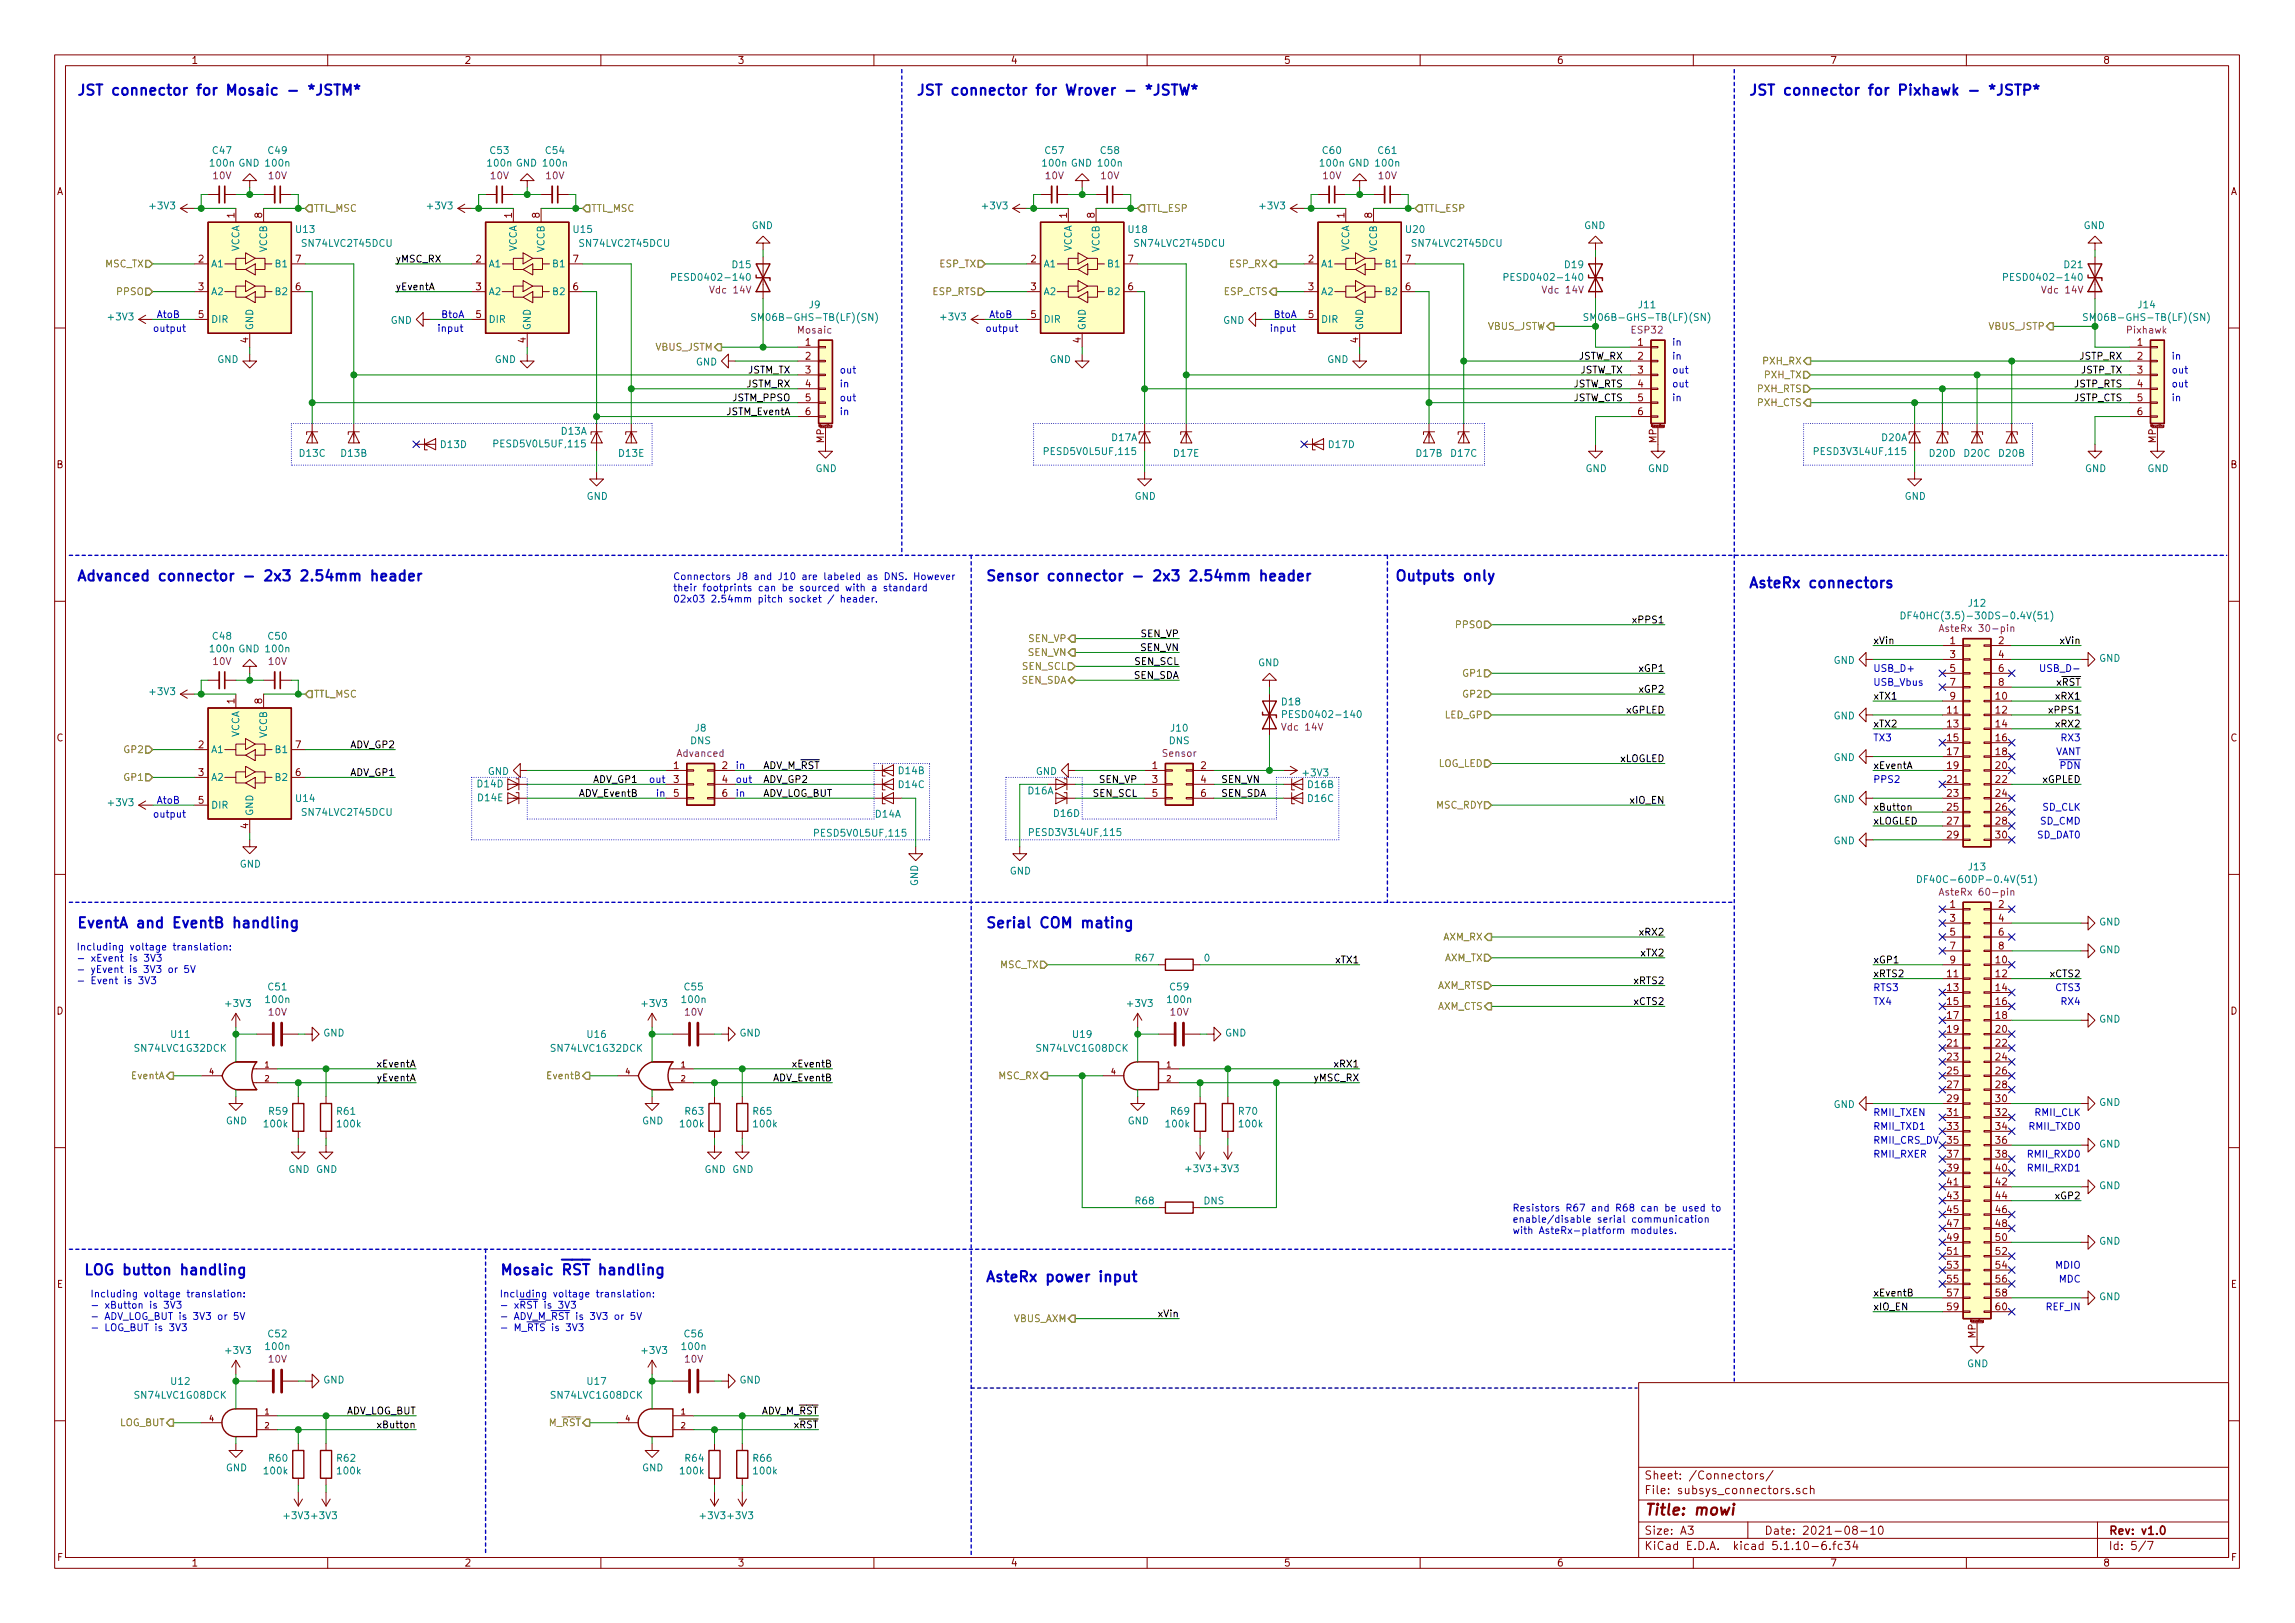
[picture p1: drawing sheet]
<svg xmlns="http://www.w3.org/2000/svg" width="420mm" height="297mm" viewBox="0 0 420 297" stroke-linecap="round" stroke-linejoin="round" font-family="sans-serif">
<defs><g id="words">
<text font-size="2.8" fill="#840000" x="301" y="277.3">Title: mowi</text>
<g font-size="2.7" fill="#0000c2">
<text x="14" y="17.5">JST connector for Mosaic - *JSTM*</text>
<text x="167.6" y="17.5">JST connector for Wrover - *JSTW*</text>
<text x="320" y="17.5">JST connector for Pixhawk - *JSTP*</text>
<text x="14" y="106.4">Advanced connector - 2x3 2.54mm header</text>
<text x="180.3" y="106.4">Sensor connector - 2x3 2.54mm header</text>
<text x="255.3" y="106.4">Outputs only</text>
<text x="320" y="107.6">AsteRx connectors</text>
<text x="14" y="169.9">EventA and EventB handling</text>
<text x="180.3" y="169.9">Serial COM mating</text>
<text x="15.2" y="233.4">LOG button handling</text>
<text x="91.4" y="233.4">Mosaic RST handling</text>
<text x="180.3" y="234.6">AsteRx power input</text>
</g>
<g font-size="2.1" fill="#840000">
<text x="301" y="273.5">File: subsys_connectors.sch</text>
<text x="301" y="270.8">Sheet: /Connectors/</text>
<text x="301" y="280.9">Size: A3</text>
<text x="323" y="280.9">Date: 2021-08-10</text>
<text x="386" y="280.9">Rev: v1.0</text>
<text x="301" y="283.7">KiCad E.D.A. kicad 5.1.10-6.fc34</text>
<text x="386" y="283.7">Id: 5/7</text>
</g>
<g font-size="1.8" fill="#840000">
<text x="35" y="11.7">1</text>
<text x="85" y="11.7">2</text>
<text x="135" y="11.7">3</text>
<text x="185" y="11.7">4</text>
<text x="235" y="11.7">5</text>
<text x="285" y="11.7">6</text>
<text x="335" y="11.7">7</text>
<text x="385" y="11.7">8</text>
<text x="10.4" y="35.7">A</text>
<text x="408.4" y="35.7">A</text>
<text x="42.9" y="39.9" transform="rotate(-90 42.9 39.9)">1</text>
<text x="48" y="39.9" transform="rotate(-90 48 39.9)">8</text>
<text x="93.7" y="39.9" transform="rotate(-90 93.7 39.9)">1</text>
<text x="98.8" y="39.9" transform="rotate(-90 98.8 39.9)">8</text>
<text x="195.3" y="39.9" transform="rotate(-90 195.3 39.9)">1</text>
<text x="200.4" y="39.9" transform="rotate(-90 200.4 39.9)">8</text>
<text x="246.1" y="39.9" transform="rotate(-90 246.1 39.9)">1</text>
<text x="251.2" y="39.9" transform="rotate(-90 251.2 39.9)">8</text>
<text x="36.3" y="48">2</text>
<text x="36.3" y="53.1">3</text>
<text x="54.1" y="53.1">6</text>
<text x="54.1" y="48">7</text>
<text x="87.1" y="48">2</text>
<text x="87.1" y="53.1">3</text>
<text x="104.9" y="53.1">6</text>
<text x="104.9" y="48">7</text>
<text x="188.7" y="48">2</text>
<text x="188.7" y="53.1">3</text>
<text x="206.5" y="53.1">6</text>
<text x="206.5" y="48">7</text>
<text x="239.5" y="48">2</text>
<text x="239.5" y="53.1">3</text>
<text x="257.3" y="53.1">6</text>
<text x="257.3" y="48">7</text>
<text x="36.3" y="58.2">5</text>
<text x="87.1" y="58.2">5</text>
<text x="188.7" y="58.2">5</text>
<text x="239.5" y="58.2">5</text>
<text x="45.5" y="62.7" transform="rotate(-90 45.5 62.7)">4</text>
<text x="96.3" y="62.7" transform="rotate(-90 96.3 62.7)">4</text>
<text x="147.5" y="63.3">1</text>
<text x="147.5" y="65.8">2</text>
<text x="197.9" y="62.7" transform="rotate(-90 197.9 62.7)">4</text>
<text x="248.7" y="62.7" transform="rotate(-90 248.7 62.7)">4</text>
<text x="299.9" y="63.3">1</text>
<text x="299.9" y="65.8">2</text>
<text x="391.3" y="63.3">1</text>
<text x="391.3" y="65.8">2</text>
<text x="147.5" y="68.4">3</text>
<text x="147.5" y="70.9">4</text>
<text x="299.9" y="68.4">3</text>
<text x="299.9" y="70.9">4</text>
<text x="391.3" y="68.4">3</text>
<text x="391.3" y="70.9">4</text>
<text x="147.5" y="73.4">5</text>
<text x="147.5" y="76">6</text>
<text x="299.9" y="73.4">5</text>
<text x="299.9" y="76">6</text>
<text x="391.3" y="73.4">5</text>
<text x="391.3" y="76">6</text>
<text x="150.9" y="81.1" transform="rotate(-90 150.9 81.1)">MP</text>
<text x="303.3" y="81.1" transform="rotate(-90 303.3 81.1)">MP</text>
<text x="394.7" y="81.1" transform="rotate(-90 394.7 81.1)">MP</text>
<text x="10.4" y="85.7">B</text>
<text x="408.4" y="85.7">B</text>
<text x="357" y="117.9">1</text>
<text x="365.9" y="117.9">2</text>
<text x="357" y="120.4">3</text>
<text x="357" y="123">5</text>
<text x="357" y="125.5">7</text>
<text x="365.9" y="120.4">4</text>
<text x="365.9" y="123">6</text>
<text x="365.9" y="125.5">8</text>
<text x="42.9" y="128.8" transform="rotate(-90 42.9 128.8)">1</text>
<text x="48" y="128.8" transform="rotate(-90 48 128.8)">8</text>
<text x="356.5" y="130.6">11</text>
<text x="357" y="128.1">9</text>
<text x="365.4" y="128.1">10</text>
<text x="365.4" y="130.6">12</text>
<text x="10.4" y="135.7">C</text>
<text x="36.3" y="136.9">2</text>
<text x="54.1" y="136.9">7</text>
<text x="356.5" y="133.1">13</text>
<text x="356.5" y="135.7">15</text>
<text x="365.4" y="133.1">14</text>
<text x="365.4" y="135.7">16</text>
<text x="408.4" y="135.7">C</text>
<text x="36.3" y="142">3</text>
<text x="54.1" y="142">6</text>
<text x="123.3" y="140.8">1</text>
<text x="123.3" y="143.3">3</text>
<text x="132.2" y="140.8">2</text>
<text x="132.2" y="143.3">4</text>
<text x="211" y="140.8">1</text>
<text x="211" y="143.3">3</text>
<text x="219.9" y="140.8">2</text>
<text x="219.9" y="143.3">4</text>
<text x="356.5" y="138.2">17</text>
<text x="356.5" y="140.8">19</text>
<text x="356.5" y="143.3">21</text>
<text x="365.4" y="138.2">18</text>
<text x="365.4" y="140.8">20</text>
<text x="365.4" y="143.3">22</text>
<text x="36.3" y="147.1">5</text>
<text x="123.3" y="145.8">5</text>
<text x="132.2" y="145.8">6</text>
<text x="211" y="145.8">5</text>
<text x="219.9" y="145.8">6</text>
<text x="356.5" y="145.8">23</text>
<text x="356.5" y="148.4">25</text>
<text x="365.4" y="145.8">24</text>
<text x="365.4" y="148.4">26</text>
<text x="45.5" y="151.6" transform="rotate(-90 45.5 151.6)">4</text>
<text x="356.5" y="150.9">27</text>
<text x="356.5" y="153.5">29</text>
<text x="365.4" y="150.9">28</text>
<text x="365.4" y="153.5">30</text>
<text x="357" y="166.2">1</text>
<text x="365.9" y="166.2">2</text>
<text x="357" y="168.7">3</text>
<text x="357" y="171.2">5</text>
<text x="357" y="173.8">7</text>
<text x="365.9" y="168.7">4</text>
<text x="365.9" y="171.2">6</text>
<text x="365.9" y="173.8">8</text>
<text x="356.5" y="178.9">11</text>
<text x="357" y="176.3">9</text>
<text x="365.4" y="176.3">10</text>
<text x="365.4" y="178.9">12</text>
<text x="10.4" y="185.7">D</text>
<text x="356.5" y="181.4">13</text>
<text x="356.5" y="183.9">15</text>
<text x="365.4" y="181.4">14</text>
<text x="365.4" y="183.9">16</text>
<text x="408.4" y="185.7">D</text>
<text x="356.5" y="186.5">17</text>
<text x="356.5" y="189">19</text>
<text x="356.5" y="191.6">21</text>
<text x="365.4" y="186.5">18</text>
<text x="365.4" y="189">20</text>
<text x="365.4" y="191.6">22</text>
<text x="356.5" y="194.1">23</text>
<text x="356.5" y="196.6">25</text>
<text x="365.4" y="194.1">24</text>
<text x="365.4" y="196.6">26</text>
<text x="356.5" y="199.2">27</text>
<text x="356.5" y="201.7">29</text>
<text x="365.4" y="199.2">28</text>
<text x="365.4" y="201.7">30</text>
<text x="356.5" y="204.3">31</text>
<text x="356.5" y="206.8">33</text>
<text x="356.5" y="209.3">35</text>
<text x="365.4" y="204.3">32</text>
<text x="365.4" y="206.8">34</text>
<text x="365.4" y="209.3">36</text>
<text x="356.5" y="211.9">37</text>
<text x="356.5" y="214.4">39</text>
<text x="365.4" y="211.9">38</text>
<text x="365.4" y="214.4">40</text>
<text x="356.5" y="217">41</text>
<text x="356.5" y="219.5">43</text>
<text x="365.4" y="217">42</text>
<text x="365.4" y="219.5">44</text>
<text x="356.5" y="222">45</text>
<text x="356.5" y="224.6">47</text>
<text x="356.5" y="227.1">49</text>
<text x="365.4" y="222">46</text>
<text x="365.4" y="224.6">48</text>
<text x="365.4" y="227.1">50</text>
<text x="356.5" y="229.7">51</text>
<text x="356.5" y="232.2">53</text>
<text x="365.4" y="229.7">52</text>
<text x="365.4" y="232.2">54</text>
<text x="10.4" y="235.7">E</text>
<text x="356.5" y="234.7">55</text>
<text x="356.5" y="237.3">57</text>
<text x="356.5" y="239.8">59</text>
<text x="365.4" y="234.7">56</text>
<text x="365.4" y="237.3">58</text>
<text x="365.4" y="239.8">60</text>
<text x="408.4" y="235.7">E</text>
<text x="361.7" y="244.9" transform="rotate(-90 361.7 244.9)">MP</text>
<text x="10.5" y="285.7">F</text>
<text x="35" y="286.7">1</text>
<text x="85" y="286.7">2</text>
<text x="135" y="286.7">3</text>
<text x="185" y="286.7">4</text>
<text x="235" y="286.7">5</text>
<text x="285" y="286.7">6</text>
<text x="335" y="286.7">7</text>
<text x="385" y="286.7">8</text>
<text x="408.5" y="285.7">F</text>
</g>
<g font-size="1.8" fill="#008484">
<text x="39" y="28.2">C47</text>
<text x="49.2" y="28.2">C49</text>
<text x="89.8" y="28.2">C53</text>
<text x="100" y="28.2">C54</text>
<text x="191.4" y="28.2">C57</text>
<text x="201.6" y="28.2">C58</text>
<text x="242.2" y="28.2">C60</text>
<text x="252.4" y="28.2">C61</text>
<text x="38.6" y="30.5">100n GND 100n</text>
<text x="89.4" y="30.5">100n GND 100n</text>
<text x="191" y="30.5">100n GND 100n</text>
<text x="241.8" y="30.5">100n GND 100n</text>
<text x="27.6" y="38.3">+3V3</text>
<text x="78.4" y="38.3">+3V3</text>
<text x="137.6" y="41.9">GND</text>
<text x="180" y="38.3">+3V3</text>
<text x="230.8" y="38.3">+3V3</text>
<text x="290" y="41.9">GND</text>
<text x="381.5" y="41.9">GND</text>
<text x="43.8" y="46.2" transform="rotate(-90 43.8 46.2)">VCCA</text>
<text x="48.9" y="46.2" transform="rotate(-90 48.9 46.2)">VCCB</text>
<text x="54.3" y="42.6">U13</text>
<text x="55.6" y="45.2">SN74LVC2T45DCU</text>
<text x="94.6" y="46.2" transform="rotate(-90 94.6 46.2)">VCCA</text>
<text x="99.7" y="46.2" transform="rotate(-90 99.7 46.2)">VCCB</text>
<text x="105.1" y="42.6">U15</text>
<text x="106.4" y="45.2">SN74LVC2T45DCU</text>
<text x="196.2" y="46.2" transform="rotate(-90 196.2 46.2)">VCCA</text>
<text x="201.3" y="46.2" transform="rotate(-90 201.3 46.2)">VCCB</text>
<text x="206.7" y="42.6">U18</text>
<text x="208" y="45.2">SN74LVC2T45DCU</text>
<text x="247" y="46.2" transform="rotate(-90 247 46.2)">VCCA</text>
<text x="252.1" y="46.2" transform="rotate(-90 252.1 46.2)">VCCB</text>
<text x="257.5" y="42.6">U20</text>
<text x="258.8" y="45.2">SN74LVC2T45DCU</text>
<text x="38.6" y="48.9">A1</text>
<text x="50.6" y="48.9">B1</text>
<text x="89.4" y="48.9">A1</text>
<text x="101.4" y="48.9">B1</text>
<text x="124" y="51.4">PESD0402-140</text>
<text x="134.1" y="49.1">D15</text>
<text x="191" y="48.9">A1</text>
<text x="203" y="48.9">B1</text>
<text x="241.8" y="48.9">A1</text>
<text x="253.8" y="48.9">B1</text>
<text x="276.4" y="51.4">PESD0402-140</text>
<text x="286.5" y="49.1">D19</text>
<text x="367.8" y="51.4">PESD0402-140</text>
<text x="378" y="49.1">D21</text>
<text x="20" y="58.6">+3V3</text>
<text x="38.6" y="54">A2</text>
<text x="38.6" y="59.1">DIR</text>
<text x="50.6" y="54">B2</text>
<text x="71.5" y="59.3">GND</text>
<text x="89.4" y="54">A2</text>
<text x="89.4" y="59.1">DIR</text>
<text x="101.4" y="54">B2</text>
<text x="139" y="58.7">SM06B-GHS-TB(LF)(SN)</text>
<text x="148.2" y="56.4">J9</text>
<text x="172.4" y="58.6">+3V3</text>
<text x="191" y="54">A2</text>
<text x="191" y="59.1">DIR</text>
<text x="203" y="54">B2</text>
<text x="223.9" y="59.3">GND</text>
<text x="241.8" y="54">A2</text>
<text x="241.8" y="59.1">DIR</text>
<text x="253.8" y="54">B2</text>
<text x="291.4" y="58.7">SM06B-GHS-TB(LF)(SN)</text>
<text x="300.1" y="56.4">J11</text>
<text x="382.9" y="58.7">SM06B-GHS-TB(LF)(SN)</text>
<text x="391.5" y="56.4">J14</text>
<text x="46.4" y="60.5" transform="rotate(-90 46.4 60.5)">GND</text>
<text x="97.2" y="60.5" transform="rotate(-90 97.2 60.5)">GND</text>
<text x="198.8" y="60.5" transform="rotate(-90 198.8 60.5)">GND</text>
<text x="249.6" y="60.5" transform="rotate(-90 249.6 60.5)">GND</text>
<text x="39.8" y="66.4">GND</text>
<text x="90.6" y="66.4">GND</text>
<text x="127.4" y="66.9">GND</text>
<text x="192.2" y="66.4">GND</text>
<text x="243" y="66.4">GND</text>
<text x="54.9" y="83.6">D13C</text>
<text x="62.5" y="83.6">D13B</text>
<text x="80.7" y="82">D13D</text>
<text x="90.9" y="81.9">PESD5V0L5UF,115</text>
<text x="102.8" y="79.6">D13A</text>
<text x="113.4" y="83.6">D13E</text>
<text x="191.6" y="83.3">PESD5V0L5UF,115</text>
<text x="203.6" y="80.7">D17A</text>
<text x="215" y="83.6">D17E</text>
<text x="243.3" y="82">D17D</text>
<text x="259.4" y="83.6">D17B</text>
<text x="265.7" y="83.6">D17C</text>
<text x="332.6" y="83.3">PESD3V3L4UF,115</text>
<text x="344.5" y="80.7">D20A</text>
<text x="353.3" y="83.6">D20D</text>
<text x="359.7" y="83.6">D20C</text>
<text x="366" y="83.6">D20B</text>
<text x="149.3" y="86.4">GND</text>
<text x="290.3" y="86.4">GND</text>
<text x="301.7" y="86.4">GND</text>
<text x="381.7" y="86.4">GND</text>
<text x="393.1" y="86.4">GND</text>
<text x="107.4" y="91.5">GND</text>
<text x="207.7" y="91.5">GND</text>
<text x="348.7" y="91.5">GND</text>
<text x="350.5" y="113.3">DF40HC(3.5)-30DS-0.4V(51)</text>
<text x="360.5" y="111">J12</text>
<text x="38.6" y="119.4">100n GND 100n</text>
<text x="39" y="117.1">C48</text>
<text x="49.2" y="117.1">C50</text>
<text x="230.3" y="121.9">GND</text>
<text x="335.7" y="121.5">GND</text>
<text x="384.3" y="121.1">GND</text>
<text x="27.6" y="127.2">+3V3</text>
<text x="234.7" y="129.1">D18</text>
<text x="235.8" y="131.4">PESD0402-140</text>
<text x="335.7" y="131.7">GND</text>
<text x="38.6" y="137.8">A1</text>
<text x="43.8" y="135.1" transform="rotate(-90 43.8 135.1)">VCCA</text>
<text x="48.9" y="135.1" transform="rotate(-90 48.9 135.1)">VCCB</text>
<text x="50.6" y="137.8">B1</text>
<text x="126.4" y="136.2">DNS</text>
<text x="127.3" y="133.9">J8</text>
<text x="214" y="136.2">DNS</text>
<text x="214.4" y="133.9">J10</text>
<text x="38.6" y="142.9">A2</text>
<text x="50.6" y="142.9">B2</text>
<text x="89.3" y="141.8">GND</text>
<text x="164.6" y="141.7">D14B</text>
<text x="189.6" y="141.8">GND</text>
<text x="238.7" y="142.1">+3V3</text>
<text x="335.7" y="139.3">GND</text>
<text x="20" y="147.5">+3V3</text>
<text x="38.6" y="148">DIR</text>
<text x="46.4" y="149.4" transform="rotate(-90 46.4 149.4)">GND</text>
<text x="54.3" y="146.8">U14</text>
<text x="55.6" y="149.3">SN74LVC2T45DCU</text>
<text x="87.5" y="144.1">D14D</text>
<text x="87.6" y="146.6">D14E</text>
<text x="160.3" y="149.6">D14A</text>
<text x="164.6" y="144.2">D14C</text>
<text x="188.2" y="145.4">D16A</text>
<text x="193" y="149.5">D16D</text>
<text x="239.5" y="146.8">D16C</text>
<text x="239.5" y="144.2">D16B</text>
<text x="335.7" y="146.9">GND</text>
<text x="149.6" y="153.1">PESD5V0L5UF,115</text>
<text x="188.9" y="153">PESD3V3L4UF,115</text>
<text x="335.7" y="154.5">GND</text>
<text x="43.9" y="158.8">GND</text>
<text x="184.9" y="160.1">GND</text>
<text x="353" y="161.6">DF40C-60DP-0.4V(51)</text>
<text x="360.5" y="159.3">J13</text>
<text x="168.1" y="162.2" transform="rotate(-90 168.1 162.2)">GND</text>
<text x="384.3" y="169.4">GND</text>
<text x="207.9" y="176">R67</text>
<text x="220.5" y="176">0</text>
<text x="384.3" y="174.5">GND</text>
<text x="41.5" y="184.3">+3V3</text>
<text x="48.8" y="183.6">100n</text>
<text x="49.2" y="181.3">C51</text>
<text x="117.7" y="184.3">+3V3</text>
<text x="125" y="183.6">100n</text>
<text x="125.4" y="181.3">C55</text>
<text x="206.6" y="184.3">+3V3</text>
<text x="213.9" y="183.6">100n</text>
<text x="214.3" y="181.3">C59</text>
<text x="31.4" y="190">U11</text>
<text x="59.2" y="189.7">GND</text>
<text x="107.6" y="190">U16</text>
<text x="135.4" y="189.7">GND</text>
<text x="196.5" y="190">U19</text>
<text x="224.3" y="189.7">GND</text>
<text x="384.3" y="187.2">GND</text>
<text x="24.9" y="192.5">SN74LVC1G32DCK</text>
<text x="101.1" y="192.5">SN74LVC1G32DCK</text>
<text x="190" y="192.5">SN74LVC1G08DCK</text>
<text x="335.7" y="202.8">GND</text>
<text x="384.3" y="202.4">GND</text>
<text x="41.4" y="205.8">GND</text>
<text x="48.5" y="206.3">100k</text>
<text x="49.3" y="204">R59</text>
<text x="61.7" y="204">R61</text>
<text x="61.9" y="206.3">100k</text>
<text x="117.6" y="205.8">GND</text>
<text x="124.7" y="206.3">100k</text>
<text x="125.5" y="204">R63</text>
<text x="137.9" y="204">R65</text>
<text x="138.1" y="206.3">100k</text>
<text x="206.5" y="205.8">GND</text>
<text x="213.6" y="206.3">100k</text>
<text x="214.4" y="204">R69</text>
<text x="226.8" y="204">R70</text>
<text x="227" y="206.3">100k</text>
<text x="52.8" y="214.7">GND GND</text>
<text x="129" y="214.7">GND GND</text>
<text x="217.2" y="214.5">+3V3 +3V3</text>
<text x="384.3" y="210">GND</text>
<text x="207.9" y="220.4">R68</text>
<text x="220.4" y="220.4">DNS</text>
<text x="384.3" y="217.6">GND</text>
<text x="384.3" y="227.8">GND</text>
<text x="384.3" y="238">GND</text>
<text x="49.2" y="244.8">C52</text>
<text x="125.4" y="244.8">C56</text>
<text x="41.5" y="247.8">+3V3</text>
<text x="48.8" y="247.1">100n</text>
<text x="117.7" y="247.8">+3V3</text>
<text x="125" y="247.1">100n</text>
<text x="360.1" y="250.2">GND</text>
<text x="24.9" y="256">SN74LVC1G08DCK</text>
<text x="31.4" y="253.5">U12</text>
<text x="59.2" y="253.2">GND</text>
<text x="101.1" y="256">SN74LVC1G08DCK</text>
<text x="107.6" y="253.5">U17</text>
<text x="135.4" y="253.2">GND</text>
<text x="41.4" y="269.3">GND</text>
<text x="48.5" y="269.8">100k</text>
<text x="49.3" y="267.5">R60</text>
<text x="61.7" y="267.5">R62</text>
<text x="61.9" y="269.8">100k</text>
<text x="117.6" y="269.3">GND</text>
<text x="124.7" y="269.8">100k</text>
<text x="125.5" y="267.5">R64</text>
<text x="137.9" y="267.5">R66</text>
<text x="138.1" y="269.8">100k</text>
<text x="52.1" y="278">+3V3 +3V3</text>
<text x="128.3" y="278">+3V3 +3V3</text>
</g>
<g font-size="1.8" fill="#840084">
<text x="39.1" y="32.8">10V</text>
<text x="49.2" y="32.8">10V</text>
<text x="89.9" y="32.8">10V</text>
<text x="100" y="32.8">10V</text>
<text x="191.5" y="32.8">10V</text>
<text x="201.6" y="32.8">10V</text>
<text x="242.3" y="32.8">10V</text>
<text x="252.4" y="32.8">10V</text>
<text x="130.3" y="53.7">Vdc 14V</text>
<text x="282.7" y="53.7">Vdc 14V</text>
<text x="374.1" y="53.7">Vdc 14V</text>
<text x="146.2" y="61">Mosaic</text>
<text x="298.8" y="61">ESP32</text>
<text x="389.5" y="61">Pixhawk</text>
<text x="356.1" y="115.7">AsteRx 30-pin</text>
<text x="39.1" y="121.7">10V</text>
<text x="49.2" y="121.7">10V</text>
<text x="235" y="133.7">Vdc 14V</text>
<text x="124.1" y="138.5">Advanced</text>
<text x="212.9" y="138.5">Sensor</text>
<text x="356.1" y="163.9">AsteRx 60-pin</text>
<text x="49.2" y="185.9">10V</text>
<text x="125.4" y="185.9">10V</text>
<text x="214.3" y="185.9">10V</text>
<text x="49.2" y="249.4">10V</text>
<text x="125.4" y="249.4">10V</text>
</g>
<g font-size="1.8" fill="#848400">
<text x="57.4" y="38.8">TTL_MSC</text>
<text x="108.2" y="38.8">TTL_MSC</text>
<text x="209.8" y="38.8">TTL_ESP</text>
<text x="260.6" y="38.8">TTL_ESP</text>
<text x="19.3" y="48.9">MSC_TX</text>
<text x="172" y="48.9">ESP_TX</text>
<text x="225.2" y="48.9">ESP_RX</text>
<text x="21.5" y="54">PPSO</text>
<text x="170.8" y="54">ESP_RTS</text>
<text x="224.1" y="54">ESP_CTS</text>
<text x="119.9" y="64.2">VBUS_JSTM</text>
<text x="272.1" y="60.4">VBUS_JSTW</text>
<text x="364.1" y="60.4">VBUS_JSTP</text>
<text x="321.8" y="71.8">PXH_RTS</text>
<text x="322.9" y="66.7">PXH_RX</text>
<text x="323.1" y="69.3">PXH_TX</text>
<text x="321.8" y="74.3">PXH_CTS</text>
<text x="188.3" y="117.5">SEN_VP</text>
<text x="266.6" y="115">PPSO</text>
<text x="187" y="125.1">SEN_SDA</text>
<text x="187.2" y="122.6">SEN_SCL</text>
<text x="188.2" y="120.1">SEN_VN</text>
<text x="268" y="123.9">GP1</text>
<text x="57.4" y="127.7">TTL_MSC</text>
<text x="264.4" y="131.5">LED_GP</text>
<text x="268" y="127.7">GP2</text>
<text x="22.9" y="137.8">GP2</text>
<text x="22.9" y="142.9">GP1</text>
<text x="263.2" y="140.4">LOG_LED</text>
<text x="262.9" y="148">MSC_RDY</text>
<text x="264.2" y="172.1">AXM_RX</text>
<text x="183.1" y="177.2">MSC_TX</text>
<text x="264.4" y="175.9">AXM_TX</text>
<text x="263.1" y="181">AXM_RTS</text>
<text x="263.1" y="184.8">AXM_CTS</text>
<text x="24.1" y="197.5">EventA</text>
<text x="100.3" y="197.5">EventB</text>
<text x="182.9" y="197.5">MSC_RX</text>
<text x="185.5" y="242">VBUS_AXM</text>
<text x="21.8" y="261">LOG_BUT</text>
<text x="100.4" y="261">M_RST</text>
</g>
<g font-size="1.8">
<text x="72.4" y="48">yMSC_RX</text>
<text x="72.4" y="53.1">yEventA</text>
<text x="288.8" y="65.8">JSTW_RX</text>
<text x="380.7" y="65.8">JSTP_RX</text>
<text x="136.6" y="70.9">JSTM_RX</text>
<text x="136.8" y="68.4">JSTM_TX</text>
<text x="287.8" y="70.9">JSTW_RTS</text>
<text x="289" y="68.4">JSTW_TX</text>
<text x="379.7" y="70.9">JSTP_RTS</text>
<text x="380.9" y="68.4">JSTP_TX</text>
<text x="133" y="76">JSTM_EventA</text>
<text x="134.2" y="73.4">JSTM_PPSO</text>
<text x="287.8" y="73.4">JSTW_CTS</text>
<text x="379.7" y="73.4">JSTP_CTS</text>
<text x="208.8" y="119.2">SEN_VN</text>
<text x="208.9" y="116.6">SEN_VP</text>
<text x="299.3" y="114.1">xPPS1</text>
<text x="342.9" y="117.9">xVin</text>
<text x="377.3" y="117.9">xVin</text>
<text x="207.5" y="124.2">SEN_SDA</text>
<text x="207.7" y="121.7">SEN_SCL</text>
<text x="300.3" y="123">xGP1</text>
<text x="376.5" y="125.5">xRST</text>
<text x="297.7" y="130.6">xGPLED</text>
<text x="300.3" y="126.8">xGP2</text>
<text x="342.9" y="128.1">xTX1</text>
<text x="375.5" y="130.6">xPPS1</text>
<text x="376.6" y="128.1">xRX1</text>
<text x="64.1" y="136.9">ADV_GP2</text>
<text x="342.9" y="133.1">xTX2</text>
<text x="376.6" y="133.1">xRX2</text>
<text x="64.1" y="142">ADV_GP1</text>
<text x="108.6" y="143.3">ADV_GP1</text>
<text x="139.7" y="140.8">ADV_M_RST</text>
<text x="139.7" y="143.3">ADV_GP2</text>
<text x="201.3" y="143.3">SEN_VP</text>
<text x="223.5" y="143.3">SEN_VN</text>
<text x="296.4" y="139.5">xLOGLED</text>
<text x="342.9" y="140.8">xEventA</text>
<text x="373.9" y="143.3">xGPLED</text>
<text x="106" y="145.8">ADV_EventB</text>
<text x="139.7" y="145.8">ADV_LOG_BUT</text>
<text x="200.1" y="145.8">SEN_SCL</text>
<text x="223.5" y="145.8">SEN_SDA</text>
<text x="298.5" y="147.1">xIO_EN</text>
<text x="342.9" y="148.4">xButton</text>
<text x="342.9" y="150.9">xLOGLED</text>
<text x="300.4" y="171.2">xRX2</text>
<text x="244.7" y="176.3">xTX1</text>
<text x="300.6" y="175">xTX2</text>
<text x="342.9" y="178.9">xRTS2</text>
<text x="342.9" y="176.3">xGP1</text>
<text x="375.5" y="178.9">xCTS2</text>
<text x="299.3" y="180.1">xRTS2</text>
<text x="299.3" y="183.9">xCTS2</text>
<text x="69.1" y="197.9">yEventA</text>
<text x="69.1" y="195.4">xEventA</text>
<text x="141.6" y="197.9">ADV_EventB</text>
<text x="145.3" y="195.4">xEventB</text>
<text x="240.6" y="197.9">yMSC_RX</text>
<text x="244.5" y="195.4">xRX1</text>
<text x="376.5" y="219.5">xGP2</text>
<text x="342.9" y="239.8">xIO_EN</text>
<text x="342.9" y="237.3">xEventB</text>
<text x="212.2" y="241.1">xVin</text>
<text x="63" y="258.9">ADV_LOG_BUT</text>
<text x="69.5" y="261.4">xButton</text>
<text x="139.1" y="258.9">ADV_M_RST</text>
<text x="145.3" y="261.4">xRST</text>
</g>
<g font-size="1.8" fill="#0000c2">
<text x="28.8" y="58.2">AtoB</text>
<text x="80.9" y="58.2">BtoA</text>
<text x="181.2" y="58.2">AtoB</text>
<text x="233.3" y="58.2">BtoA</text>
<text x="27.9" y="60.7">output</text>
<text x="80" y="60.7">input</text>
<text x="180.3" y="60.7">output</text>
<text x="232.4" y="60.7">input</text>
<text x="306.1" y="65.8">in</text>
<text x="306.1" y="63.3">in</text>
<text x="397.5" y="65.8">in</text>
<text x="153.7" y="68.4">out</text>
<text x="153.7" y="70.9">in</text>
<text x="306.1" y="68.4">out</text>
<text x="306.1" y="70.9">out</text>
<text x="397.5" y="70.9">out</text>
<text x="397.5" y="68.4">out</text>
<text x="153.7" y="76">in</text>
<text x="153.7" y="73.4">out</text>
<text x="306.1" y="73.4">in</text>
<text x="397.5" y="73.4">in</text>
<text x="123.2" y="106.2">Connectors J8 and J10 are labeled as DNS. However</text>
<text x="123.2" y="108.2">their footprints can be sourced with a standard</text>
<text x="123.2" y="110.3">02x03 2.54mm pitch socket / header.</text>
<text x="342.9" y="123">USB_D+</text>
<text x="342.9" y="125.5">USB_Vbus</text>
<text x="374.4" y="123">USB_D-</text>
<text x="342.9" y="135.7">TX3</text>
<text x="377.6" y="135.7">RX3</text>
<text x="119.2" y="143.3">out</text>
<text x="134.6" y="140.8">in</text>
<text x="134.6" y="143.3">out</text>
<text x="342.9" y="143.3">PPS2</text>
<text x="376.2" y="138.2">VANT</text>
<text x="377.3" y="140.8">PDN</text>
<text x="27.9" y="149.6">output</text>
<text x="28.8" y="147.1">AtoB</text>
<text x="120.3" y="145.8">in</text>
<text x="134.6" y="145.8">in</text>
<text x="373.9" y="148.4">SD_CLK</text>
<text x="372.9" y="153.5">SD_DAT0</text>
<text x="373.5" y="150.9">SD_CMD</text>
<text x="14" y="174">Including voltage translation:</text>
<text x="14" y="176">- xEvent is 3V3</text>
<text x="14" y="178.1">- yEvent is 3V3 or 5V</text>
<text x="14" y="180.1">- Event is 3V3</text>
<text x="342.9" y="181.4">RTS3</text>
<text x="342.9" y="183.9">TX4</text>
<text x="376.5" y="181.4">CTS3</text>
<text x="377.6" y="183.9">RX4</text>
<text x="342.9" y="209.3">RMII_CRS_DV</text>
<text x="342.9" y="206.8">RMII_TXD1</text>
<text x="342.9" y="204.3">RMII_TXEN</text>
<text x="371.8" y="206.8">RMII_TXD0</text>
<text x="372.6" y="204.3">RMII_CLK</text>
<text x="342.9" y="211.9">RMII_RXER</text>
<text x="371.6" y="214.4">RMII_RXD1</text>
<text x="371.6" y="211.9">RMII_RXD0</text>
<text x="276.9" y="221.7">Resistors R67 and R68 can be used to</text>
<text x="276.9" y="223.8">enable/disable serial communication</text>
<text x="276.9" y="225.8">with AsteRx-platform modules.</text>
<text x="376.4" y="232.2">MDIO</text>
<text x="16.5" y="237.5">Including voltage translation:</text>
<text x="16.5" y="239.5">- xButton is 3V3</text>
<text x="91.4" y="237.5">Including voltage translation:</text>
<text x="91.4" y="239.5">- xRST is 3V3</text>
<text x="374.7" y="239.8">REF_IN</text>
<text x="377" y="234.7">MDC</text>
<text x="16.5" y="241.6">- ADV_LOG_BUT is 3V3 or 5V</text>
<text x="16.5" y="243.6">- LOG_BUT is 3V3</text>
<text x="91.4" y="241.6">- ADV_M_RST is 3V3 or 5V</text>
<text x="91.4" y="243.6">- M_RTS is 3V3</text>
</g>
<g font-size="1.4" fill="#840000">
<text x="38.4" y="196.6">4</text>
<text x="48.5" y="195.4">1</text>
<text x="48.5" y="197.9">2</text>
<text x="114.6" y="196.6">4</text>
<text x="124.7" y="195.4">1</text>
<text x="124.7" y="197.9">2</text>
<text x="203.5" y="196.6">4</text>
<text x="213.6" y="195.4">1</text>
<text x="213.6" y="197.9">2</text>
<text x="38.4" y="260.1">4</text>
<text x="48.5" y="258.9">1</text>
<text x="48.5" y="261.4">2</text>
<text x="114.6" y="260.1">4</text>
<text x="124.7" y="258.9">1</text>
<text x="124.7" y="261.4">2</text>
</g>
<g font-size=".5" fill="#840000">
<text x="149.9" y="78.1">Mounting</text>
<text x="302.3" y="78.1">Mounting</text>
<text x="393.8" y="78.1">Mounting</text>
<text x="360.8" y="241.9">Mounting</text>
</g>
</g></defs>
<g fill="none" stroke="#840000" stroke-width=".18">
<path d="M10 10h400v277h-400zM12 12h396v273.1h-396zM60 10v2M110 10v2M160 10v2M210 10v2M260 10v2M310 10v2M360 10v2M33 38.1h2.6M33 38.1l1.3 .8M34.3 37.4l-1.3 .7"/>
<path d="M38.1 35.6h2M41.1 35.6h2.1M43.2 38.1v2.6M45.7 33.1h1.3l-1.3-1.3-1.3 1.3h1.3v1.2M48.3 38.1v2.6M48.3 35.6h2M51.3 35.6h2M83.8 38.1l1.3 .8M83.8 38.1h2.6M85.1 37.4l-1.3 .7M88.9 35.6h2M91.9 35.6h2.1"/>
<path d="M94 38.1v2.6M96.5 33.1h1.3l-1.3-1.3-1.3 1.3h1.3v1.2M99.1 35.6h2M99.1 38.1v2.6M102.1 35.6h2M185.4 38.1h2.6M185.4 38.1l1.3 .8M186.7 37.4l-1.3 .7M190.5 35.6h2M193.5 35.6h2.1M195.6 38.1v2.6M198.1 33.1h1.3l-1.3-1.3-1.3 1.3h1.3v1.2"/>
<path d="M200.7 35.6h2M200.7 38.1v2.6M203.7 35.6h2M236.2 38.1h2.6M236.2 38.1l1.3 .8M237.5 37.4l-1.3 .7M241.3 35.6h2M244.3 35.6h2.1M246.4 38.1v2.6M248.9 33.1h1.3l-1.3-1.3-1.3 1.3h1.3v1.2M251.5 35.6h2M251.5 38.1v2.6"/>
<path d="M254.5 35.6h2M25.4 58.5h2.5M25.4 58.5l1.3 .7M26.7 57.7l-1.3 .8M35.6 48.3h2.5M35.6 53.4h2.5M35.6 58.5h2.5M41.1 48.3h2.1v1h1.8M41.1 53.4h2.1v1h1.8M45 47.3h-1.8v1M45 46.3l1.7 1-1.7 1zM45 49.3l1.7-1v2z"/>
<path d="M45 52.4h-1.8v1M45 51.3l1.7 1.1-1.7 1zM45 54.4l1.7-1v2zM46.7 47.3h1.8v1h1.3M46.7 52.4h1.8v1h1.3M48.5 48.3v1h-1.8M48.5 53.4v1h-1.8M53.3 48.3h2.6M53.3 53.4h2.6M77.5 58.5v-1.3l-1.3 1.3 1.3 1.2v-1.2h1.2M86.4 48.3h2.5M86.4 53.4h2.5"/>
<path d="M86.4 58.5h2.5M91.9 48.3h2.1v1h1.8M91.9 53.4h2.1v1h1.8M95.8 47.3h-1.8v1M95.8 46.3l1.7 1-1.7 1zM95.8 49.3l1.7-1v2zM95.8 52.4h-1.8v1M95.8 51.3l1.7 1.1-1.7 1zM95.8 54.4l1.7-1v2zM97.5 47.3h1.8v1h1.3M97.5 52.4h1.8v1h1.3M99.3 48.3v1h-1.8"/>
<path d="M99.3 53.4v1h-1.8M104.1 48.3h2.6M104.1 53.4h2.6M139.7 44.5h1.3l-1.3-1.3-1.3 1.3h1.3v1.3M139.7 47v7.6M177.8 58.5h2.5M177.8 58.5l1.3 .7M179.1 57.7l-1.3 .8M188 48.3h2.5M188 53.4h2.5M188 58.5h2.5M193.5 48.3h2.1v1h1.8"/>
<path d="M193.5 53.4h2.1v1h1.8M197.4 47.3h-1.8v1M197.4 46.3l1.7 1-1.7 1zM197.4 49.3l1.7-1v2zM197.4 52.4h-1.8v1M197.4 51.3l1.7 1.1-1.7 1zM197.4 54.4l1.7-1v2zM199.1 47.3h1.8v1h1.3M199.1 52.4h1.8v1h1.3M200.9 48.3v1h-1.8M200.9 53.4v1h-1.8M205.7 48.3h2.6"/>
<path d="M205.7 53.4h2.6M229.9 58.5v-1.3l-1.3 1.3 1.3 1.2v-1.2h1.2M238.8 48.3h2.5M238.8 53.4h2.5M238.8 58.5h2.5M244.3 48.3h2.1v1h1.8M244.3 53.4h2.1v1h1.8M248.2 47.3h-1.8v1M248.2 46.3l1.7 1-1.7 1zM248.2 49.3l1.7-1v2zM248.2 52.4h-1.8v1M248.2 51.3l1.7 1.1-1.7 1z"/>
<path d="M248.2 54.4l1.7-1v2zM249.9 47.3h1.8v1h1.3M249.9 52.4h1.8v1h1.3M251.7 48.3v1h-1.8M251.7 53.4v1h-1.8M256.5 48.3h2.6M256.5 53.4h2.6M292.1 44.5h1.3l-1.3-1.3-1.3 1.3h1.3v1.3M292.1 47v7.6M383.5 44.5h1.3l-1.3-1.3-1.2 1.3h1.2v1.3M383.5 47v7.6M10 60h2"/>
<path d="M45.7 64.8v1.3h1.3l-1.3 1.2-1.3-1.2h1.3M45.7 61v2.5M57.1 79l1.1 2.1h-2.1zM57.1 77.5v3.6M58.2 79h-2.1v.5M64.8 79l1 2.1h-2zM64.8 77.5v3.6M65.8 79h-2v.5M96.5 64.8v1.3h1.3l-1.3 1.2-1.3-1.2h1.3M96.5 61v2.5M109.2 79l1 2.1h-2zM109.2 77.5v5.1"/>
<path d="M110.2 79h-2v.5M115.6 79l1 2.1h-2zM115.6 77.5v3.6M116.6 79h-2v.5M133.3 66.1v-1.3l-1.2 1.3 1.2 1.2v-1.2h1.3M146 63.5h3.9M146 66.1h3.9M146 68.6h3.9M146 71.2h3.9M146 73.7h3.9M146 76.2h3.9M149.9 73.6h1.2v.2h-1.2z"/>
<path d="M149.9 76.1h1.2v.3h-1.2zM149.9 71h1.2v.3h-1.2zM149.9 65.9h1.2v.3h-1.2zM149.9 63.4h1.2v.3h-1.2zM149.9 68.5h1.2v.2h-1.2zM150.1 78.3h2M151.1 78.3v4.3h1.3l-1.3 1.3-1.2-1.3h1.2M152.3 78.1l-.2-.1 .1-.2h.1v.4h-.2M198.1 64.8v1.3h1.3l-1.3 1.2-1.3-1.2h1.3M198.1 61v2.5M209.5 79l1.1 2.1h-2.1zM209.5 77.5v5.1"/>
<path d="M210.6 79h-2.1v.5M217.2 79l1 2.1h-2zM217.2 77.5v3.6M218.2 79h-2v.5M248.9 64.8v1.3h1.3l-1.3 1.2-1.3-1.2h1.3M248.9 61v2.5M261.6 79l1 2.1h-2zM261.6 77.5v3.6M262.6 79h-2v.5M268 79l1 2.1h-2zM268 77.5v3.6M269 79h-2v.5"/>
<path d="M298.4 63.5h3.9M298.4 66.1h3.9M298.4 68.6h3.9M298.4 71.2h3.9M298.4 73.7h3.9M298.4 76.2h3.9M302.3 73.6h1.2v.2h-1.2zM302.3 76.1h1.2v.3h-1.2zM302.3 71h1.2v.3h-1.2zM302.3 65.9h1.2v.3h-1.2zM302.3 63.4h1.2v.3h-1.2zM302.3 68.5h1.2v.2h-1.2z"/>
<path d="M302.5 78.3h2M303.5 78.3v4.3h1.3l-1.3 1.3-1.2-1.3h1.2M304.7 78.1l-.2-.1 .1-.2h.1v.4h-.2M350.5 79l1 2.1h-2zM350.5 77.5v5.1M351.5 79h-2v.5M354.6 79h2v.5M355.6 79l1 2.1h-2zM355.6 77.5v3.6M360.9 79h2.1v.5M361.9 79l1.1 2.1h-2.1zM361.9 77.5v3.6"/>
<path d="M367.3 79h2v.5M368.3 79l1 2.1h-2zM368.3 77.5v3.6M389.9 63.5h3.8M389.9 66.1h3.8M389.9 68.6h3.8M389.9 71.2h3.8M389.9 73.7h3.8M389.9 76.2h3.8M393.7 73.6h1.3v.2h-1.3zM393.7 76.1h1.3v.3h-1.3zM393.7 71h1.3v.3h-1.3z"/>
<path d="M393.7 65.9h1.3v.3h-1.3zM393.7 63.4h1.3v.3h-1.3zM393.7 68.5h1.3v.2h-1.3zM394 78.3h2M395 78.3v4.3h1.2l-1.2 1.3-1.3-1.3h1.3M396.1 78.1l-.1-.1v-.2h.1v.4h-.1M408 60h2M76.2 81.3h3.6M77.7 80.3v2h.5M77.7 81.3l2.1-1v2zM109.2 86.4v1.3h1.3l-1.3 1.2-1.3-1.2h1.3M209.5 86.4v1.3h1.3l-1.3 1.2-1.2-1.2h1.2"/>
<path d="M238.8 81.3h3.5M240.3 80.3v2h.5M240.3 81.3l2-1v2zM292.1 81.3v1.3h1.3l-1.3 1.3-1.3-1.3h1.3M350.5 86.4v1.3h1.3l-1.3 1.2-1.3-1.2h1.3M383.5 81.3v1.3h1.3l-1.3 1.3-1.2-1.3h1.2M10 110h2M355.6 118.1h3.8M359.4 118h1.3v.3h-1.3zM363.2 118h1.3v.3h-1.3zM364.5 118.1h3.8M408 110h2"/>
<path d="M33 127l1.3 .8M33 127h2.6M34.3 126.3l-1.3 .7M35.6 137.2h2.5M38.1 124.5h2M41.1 137.2h2.1v1h1.8M41.1 124.5h2.1M43.2 127v2.6M45 136.2h-1.8v1M45 135.2l1.7 1-1.7 1zM45 138.2l1.7-1v2zM45.7 122h1.3l-1.3-1.3-1.3 1.3h1.3v1.2"/>
<path d="M46.7 136.2h1.8v1h1.3M48.3 127v2.6M48.3 124.5h2M48.5 137.2v1h-1.8M51.3 124.5h2M53.3 137.2h2.6M161.5 140v2h.6M232.4 124.5h1.3l-1.3-1.3-1.3 1.3h1.3v1.3M232.4 127v7.7M341.6 138.5v-1.3l-1.2 1.3 1.2 1.2v-1.2h1.3M341.6 130.8v-1.2l-1.2 1.2 1.2 1.3v-1.3h1.3M341.6 120.7v-1.3l-1.2 1.3 1.2 1.3v-1.3h1.3"/>
<path d="M355.6 128.3h3.8M355.6 130.8h3.8M355.6 133.4h3.8M355.6 135.9h3.8M355.6 138.5h3.8M355.6 120.7h3.8M355.6 123.2h3.8M355.6 125.8h3.8M359.4 138.3h1.3v.3h-1.3zM359.4 133.3h1.3v.2h-1.3zM359.4 130.7h1.3v.3h-1.3zM359.4 128.2h1.3v.2h-1.3z"/>
<path d="M359.4 125.6h1.3v.3h-1.3zM359.4 135.8h1.3v.3h-1.3zM359.4 123.1h1.3v.3h-1.3zM359.4 120.6h1.3v.2h-1.3zM363.2 138.3h1.3v.3h-1.3zM363.2 133.3h1.3v.2h-1.3zM363.2 130.7h1.3v.3h-1.3zM363.2 128.2h1.3v.2h-1.3zM363.2 125.6h1.3v.3h-1.3zM363.2 135.8h1.3v.3h-1.3zM363.2 123.1h1.3v.3h-1.3zM363.2 120.6h1.3v.2h-1.3z"/>
<path d="M364.5 128.3h3.8M364.5 130.8h3.8M364.5 133.4h3.8M364.5 135.9h3.8M364.5 138.5h3.8M364.5 120.7h3.8M364.5 123.2h3.8M364.5 125.8h3.8M381 120.7h1.3v-1.3l1.2 1.3-1.2 1.3v-1.3M25.4 147.4l1.3 .7M25.4 147.4h2.5M26.7 146.6l-1.3 .8"/>
<path d="M35.6 147.4h2.5M35.6 142.3h2.5M41.1 142.3h2.1v1h1.8M45 141.3h-1.8v1M45 140.2l1.7 1.1-1.7 1zM45 143.3l1.7-1v2zM45.7 153.7v1.3h1.3l-1.3 1.2-1.3-1.2h1.3M45.7 149.9v2.5M46.7 141.3h1.8v1h1.3M48.5 142.3v1h-1.8M53.3 142.3h2.6M93 142.5l2 1-2 1.1z"/>
<path d="M93 145.1l2 1-2 1zM93 143.5h3.5M93 146.1h3.5M94.5 142.5h.5v2.1M94.5 145.1h.5v2M95.2 141v-1.3l-1.2 1.3 1.2 1.3v-1.3h1.3M121.9 141h3.8M121.9 143.5h3.8M121.9 146.1h3.8M125.7 146h1.3v.2h-1.3zM125.7 140.9h1.3v.2h-1.3zM125.7 143.4h1.3v.3h-1.3z"/>
<path d="M129.5 146h1.3v.2h-1.3zM129.5 140.9h1.3v.2h-1.3zM129.5 143.4h1.3v.3h-1.3zM130.8 141h3.8M130.8 143.5h3.8M130.8 146.1h3.8M160 141h3.6M160 143.5h3.6M160 146.1h5.1M161.5 141l2.1-1v2zM161.5 142.5v2.1h.6M161.5 143.5l2.1-1v2.1z"/>
<path d="M161.5 145.1v2h.6M161.5 146.1l2.1-1v2zM167.6 155v1.2h-1.2l1.2 1.3 1.3-1.3h-1.3M186.7 155v1.2h1.3l-1.3 1.3-1.3-1.3h1.3M191.8 143.5h5M193.3 145.1l2 1-2 1zM193.3 142.5l2 1-2 1.1zM193.3 146.1h3.5M194.8 145.1h.5v2M194.8 142.5h.5v2.1M195.6 141v-1.3l-1.3 1.3 1.3 1.3v-1.3h1.2M209.5 141h3.9"/>
<path d="M209.5 143.5h3.9M209.5 146.1h3.9M213.4 146h1.2v.2h-1.2zM213.4 140.9h1.2v.2h-1.2zM213.4 143.4h1.2v.3h-1.2zM217.2 146h1.2v.2h-1.2zM217.2 140.9h1.2v.2h-1.2zM217.2 143.4h1.2v.3h-1.2zM218.4 141h3.8M218.4 143.5h3.8M218.4 146.1h3.8M234.9 141h2.6"/>
<path d="M234.9 143.5h3.6M234.9 146.1h3.6M236.2 140.2l1.3 .8M236.5 145.1v2h.5M236.5 146.1l2-1v2zM236.5 142.5v2.1h.5M236.5 143.5l2-1v2.1zM237.5 141l-1.3 .8M341.6 146.1v-1.3l-1.2 1.3 1.2 1.3v-1.3h1.3M341.6 153.7v-1.3l-1.2 1.3 1.2 1.3v-1.3h1.3M355.6 141h3.8M355.6 143.5h3.8"/>
<path d="M355.6 146.1h3.8M355.6 148.6h3.8M355.6 151.2h3.8M355.6 153.7h3.8M359.4 140.9h1.3v.2h-1.3zM359.4 143.4h1.3v.3h-1.3zM359.4 146h1.3v.2h-1.3zM359.4 148.5h1.3v.3h-1.3zM359.4 151h1.3v.3h-1.3zM359.4 153.6h1.3v.2h-1.3zM363.2 140.9h1.3v.2h-1.3zM363.2 143.4h1.3v.3h-1.3z"/>
<path d="M363.2 146h1.3v.2h-1.3zM363.2 148.5h1.3v.3h-1.3zM363.2 151h1.3v.3h-1.3zM363.2 153.6h1.3v.2h-1.3zM364.5 141h3.8M364.5 143.5h3.8M364.5 146.1h3.8M364.5 148.6h3.8M364.5 151.2h3.8M364.5 153.7h3.8M10 160h2M212.1 176.6h1.3"/>
<path d="M218.4 176.6h1.3M355.6 166.4h3.8M355.6 176.6h3.8M355.6 179.1h3.8M355.6 168.9h3.8M355.6 171.5h3.8M355.6 174h3.8M359.4 176.4h1.3v.3h-1.3zM359.4 173.9h1.3v.3h-1.3zM359.4 171.4h1.3v.2h-1.3zM359.4 168.8h1.3v.3h-1.3zM359.4 166.3h1.3v.2h-1.3z"/>
<path d="M359.4 179h1.3v.2h-1.3zM363.2 176.4h1.3v.3h-1.3zM363.2 173.9h1.3v.3h-1.3zM363.2 171.4h1.3v.2h-1.3zM363.2 168.8h1.3v.3h-1.3zM363.2 166.3h1.3v.2h-1.3zM363.2 179h1.3v.2h-1.3zM364.5 166.4h3.8M364.5 176.6h3.8M364.5 179.1h3.8M364.5 168.9h3.8M364.5 171.5h3.8"/>
<path d="M364.5 174h3.8M381 174h1.3v-1.2l1.2 1.2-1.2 1.3v-1.3M381 168.9h1.3v-1.2l1.2 1.2-1.2 1.3v-1.3M408 160h2M36.8 196.9h3.8M43.2 185.5v2.5M43.2 185.5l-.8 1.2M43.2 185.5l.7 1.2M46.4 198.2h4.4M46.4 195.6h4.4M47 189.3h2.8M51.8 189.3h2.8"/>
<path d="M55.9 189.3h1.2v-1.3l1.3 1.3-1.3 1.2v-1.2M113 196.9h3.8M119.4 185.5v2.5M119.4 185.5l-.8 1.2M119.4 185.5l.7 1.2M122.6 198.2h4.4M122.6 195.6h4.4M123.2 189.3h2.8M128 189.3h2.8M132.1 189.3h1.2v-1.3l1.3 1.3-1.3 1.2v-1.2M201.9 196.9h3.8M208.3 185.5l-.8 1.2"/>
<path d="M208.3 185.5v2.5M208.3 185.5l.7 1.2M212.1 189.3h2.8M212.1 198.2h3.8M212.1 195.6h3.8M216.9 189.3h2.8M221 189.3h1.2v-1.3l1.3 1.3-1.3 1.2v-1.2M355.6 181.6h3.8M355.6 184.2h3.8M355.6 186.7h3.8M355.6 189.3h3.8M355.6 191.8h3.8"/>
<path d="M355.6 194.3h3.8M355.6 196.9h3.8M355.6 199.4h3.8M359.4 199.3h1.3v.3h-1.3zM359.4 196.8h1.3v.2h-1.3zM359.4 194.2h1.3v.3h-1.3zM359.4 191.7h1.3v.2h-1.3zM359.4 189.1h1.3v.3h-1.3zM359.4 186.6h1.3v.3h-1.3zM359.4 184.1h1.3v.2h-1.3zM359.4 181.5h1.3v.3h-1.3zM363.2 199.3h1.3v.3h-1.3z"/>
<path d="M363.2 196.8h1.3v.2h-1.3zM363.2 194.2h1.3v.3h-1.3zM363.2 191.7h1.3v.2h-1.3zM363.2 189.1h1.3v.3h-1.3zM363.2 186.6h1.3v.3h-1.3zM363.2 184.1h1.3v.2h-1.3zM363.2 181.5h1.3v.3h-1.3zM364.5 181.6h3.8M364.5 184.2h3.8M364.5 186.7h3.8M364.5 189.3h3.8M364.5 191.8h3.8"/>
<path d="M364.5 194.3h3.8M364.5 196.9h3.8M364.5 199.4h3.8M381 186.7h1.3v-1.2l1.2 1.2-1.2 1.3v-1.3M10 210h2M43.2 200.7v1.3h1.2l-1.2 1.2-1.3-1.2h1.3M54.6 209.6v1.3h1.3l-1.3 1.2-1.3-1.2h1.3M54.6 200.7v1.3M54.6 207v1.3M59.7 209.6v1.3h1.3l-1.3 1.2-1.3-1.2h1.3M59.7 200.7v1.3M59.7 207v1.3"/>
<path d="M119.4 200.7v1.3h1.2l-1.2 1.2-1.3-1.2h1.3M130.8 209.6v1.3h1.3l-1.3 1.2-1.3-1.2h1.3M130.8 200.7v1.3M130.8 207v1.3M135.9 209.6v1.3h1.3l-1.3 1.2-1.3-1.2h1.3M135.9 200.7v1.3M135.9 207v1.3M208.3 200.7v1.3h1.2l-1.2 1.2-1.3-1.2h1.3M218.9 210.9l.8 1.2M219.7 200.7v1.3M219.7 207v1.3M219.7 209.6v2.5"/>
<path d="M220.5 210.9l-.8 1.2M224 210.9l.8 1.2M224.8 200.7v1.3M224.8 207v1.3M224.8 209.6v2.5M225.6 210.9l-.8 1.2M341.6 202v-1.3l-1.2 1.3 1.2 1.2v-1.2h1.3M355.6 202h3.8M355.6 204.5h3.8M355.6 207h3.8M355.6 209.6h3.8M355.6 212.1h3.8"/>
<path d="M355.6 214.7h3.8M355.6 217.2h3.8M355.6 219.7h3.8M359.4 206.9h1.3v.3h-1.3zM359.4 209.5h1.3v.2h-1.3zM359.4 212h1.3v.3h-1.3zM359.4 214.5h1.3v.3h-1.3zM359.4 217.1h1.3v.2h-1.3zM359.4 219.6h1.3v.3h-1.3zM359.4 204.4h1.3v.2h-1.3zM359.4 201.8h1.3v.3h-1.3zM363.2 206.9h1.3v.3h-1.3z"/>
<path d="M363.2 209.5h1.3v.2h-1.3zM363.2 212h1.3v.3h-1.3zM363.2 214.5h1.3v.3h-1.3zM363.2 217.1h1.3v.2h-1.3zM363.2 219.6h1.3v.3h-1.3zM363.2 204.4h1.3v.2h-1.3zM363.2 201.8h1.3v.3h-1.3zM364.5 202h3.8M364.5 204.5h3.8M364.5 207h3.8M364.5 209.6h3.8M364.5 212.1h3.8"/>
<path d="M364.5 214.7h3.8M364.5 217.2h3.8M364.5 219.7h3.8M381 202h1.3v-1.3l1.2 1.3-1.2 1.2v-1.2M381 209.6h1.3v-1.3l1.2 1.3-1.2 1.3v-1.3M381 217.2h1.3v-1.3l1.2 1.3-1.2 1.3v-1.3M408 210h2M212.1 221h1.3M218.4 221h1.3M355.6 222.3h3.8M355.6 224.8h3.8M355.6 227.4h3.8"/>
<path d="M355.6 229.9h3.8M355.6 232.4h3.8M355.6 235h3.8M355.6 237.5h3.8M359.4 229.8h1.3v.2h-1.3zM359.4 232.3h1.3v.3h-1.3zM359.4 234.9h1.3v.2h-1.3zM359.4 237.4h1.3v.3h-1.3zM359.4 239.9h1.3v.3h-1.3zM359.4 222.2h1.3v.2h-1.3zM359.4 224.7h1.3v.3h-1.3zM359.4 227.2h1.3v.3h-1.3z"/>
<path d="M363.2 229.8h1.3v.2h-1.3zM363.2 232.3h1.3v.3h-1.3zM363.2 234.9h1.3v.2h-1.3zM363.2 237.4h1.3v.3h-1.3zM363.2 239.9h1.3v.3h-1.3zM363.2 222.2h1.3v.2h-1.3zM363.2 224.7h1.3v.3h-1.3zM363.2 227.2h1.3v.3h-1.3zM364.5 222.3h3.8M364.5 224.8h3.8M364.5 227.4h3.8M364.5 229.9h3.8"/>
<path d="M364.5 232.4h3.8M364.5 235h3.8M364.5 237.5h3.8M381 227.4h1.3v-1.3l1.2 1.3-1.2 1.2v-1.2M381 237.5h1.3v-1.2l1.2 1.2-1.2 1.3v-1.3M43.2 249l-.8 1.2M43.2 249v2.5M43.2 249l.7 1.2M47 259.1h3.8M47 252.8h2.8M51.8 252.8h2.8M55.9 252.8h1.2v-1.3l1.3 1.3-1.3 1.2v-1.2"/>
<path d="M119.4 249l-.8 1.2M119.4 249v2.5M119.4 249l.7 1.2M123.2 259.1h3.8M123.2 252.8h2.8M128 252.8h2.8M132.1 252.8h1.2v-1.3l1.3 1.3-1.3 1.2v-1.2M300 253h108v32.1h-108zM355.6 240.1h3.8M360.9 242.1h2.1M361.9 242.1v4.3h1.3l-1.3 1.3-1.2-1.3h1.2M363.1 241.7v.3h-.1"/>
<path d="M363.1 241.7h-.2l.2 .2M364.5 240.1h3.8M10 260h2M36.8 260.4h3.8M43.2 264.2v1.3h1.2l-1.2 1.2-1.3-1.2h1.3M47 261.7h3.8M53.8 274.4l.8 1.2M54.6 264.2v1.3M54.6 270.5v1.3M54.6 273.1v2.5M55.4 274.4l-.8 1.2M58.9 274.4l.8 1.2"/>
<path d="M59.7 264.2v1.3M59.7 270.5v1.3M59.7 273.1v2.5M60.5 274.4l-.8 1.2M113 260.4h3.8M119.4 264.2v1.3h1.2l-1.2 1.2-1.3-1.2h1.3M123.2 261.7h3.8M130 274.4l.8 1.2M130.8 264.2v1.3M130.8 270.5v1.3M130.8 273.1v2.5M131.6 274.4l-.8 1.2"/>
<path d="M135.1 274.4l.8 1.2M135.9 264.2v1.3M135.9 270.5v1.3M135.9 273.1v2.5M136.7 274.4l-.8 1.2M300 278.5h108M300 274.5h108M300 268.5h108M309 279.3h1l-.5 .6 .4 .1v.7l-.2 .1-.7-.1M320 278.5v3M320 269.8l.2-.1 .5 .1v.8l-.2 .1-.5-.1zM321.4 269.7v1"/>
<path d="M321.8 269.7l-.4 .3M322.8 269.8l-.3-.1-.3 .2 .1 .2 .5 .2v.3h-.6M324.6 269.1l-1.3 2M328.2 273.3v.1M329.5 272.5a.37 .37 0 0 0-.6 .1l.1 .2 .5 .2v.1l-.2 .3-.4-.1M330.8 272.5l-.4-.1-.3 .3 .1 .6 .2 .1 .4-.1M331.4 272.5h.1a.37 .37 0 0 1 .6 .1v.8M331.4 271.9v1.5M339.5 279.9l-.3-.2v-.2l.3-.2 .4 .1 .1 .2-.1 .3h-.4l-.3 .3v.5l.3 .1 .4-.1 .1-.2v-.3l-.2-.3M342.5 279.7l.4-.4v1.5M344.1 279.4l.1-.1a.8 .8 0 0 1 .6 .8 .8 .8 0 0 1-.6 .7 1 1 0 0 1-.1-1.4zM384 278.5v6.6"/>
<path d="M408 260h2M60 285.1v1.9M110 285.1v1.9M160 285.1v1.9M210 285.1v1.9M260 285.1v1.9M300 281.5h108M310 285.1v1.9M331.7 283h1.2M334.2 282.1a.59 .59 0 0 0-.7 .6v.6l.2 .2 .4 .1 .2-.1 .1-.5-.2-.3h-.4l-.3 .3M335 283.5v.1M335.5 282.6h.6"/>
<path d="M336.1 282.1l-.4 .2v1.3M337.2 282.7l-.4-.1-.3 .3 .2 .6h.5M337.7 282.1h1l-.5 .6 .4 .1v.7l-.2 .1-.7-.1M339.6 282l-.4 1.1h1M340 282.6v1M340.7 280.2h1.1M342.5 280.8h.8M360 285.1v1.9M392.8 282l-1.3 2M393.2 282.1h1l-.7 1.5"/>
</g>
<path d="M41.1 34.1v3M51.3 34.1v3M91.9 34.1v3M102.1 34.1v3M193.5 34.1v3M203.7 34.1v3M244.3 34.1v3M254.5 34.1v3M41.1 123v3M51.3 123v3M395.7 279.5l.2-.2a.81 .81 0 0 1 .6 .6 .81 .81 0 0 1-.3 .8l-.2 .1a.79 .79 0 0 1-.3-1.3z" fill="none" stroke="#840000" stroke-width=".3"/>
<path d="M317.4 275.9l-.2 1.3M317.4 275.2l-.1 .1 .1 .1 .2-.1-.2-.1v.2" fill="none" stroke="#840000" stroke-width=".41"/>
<g fill="none" stroke="#840000" stroke-width=".25">
<path d="M38.1 40.7h15.2v20.3h-15.2zM88.9 40.7h15.2v20.3h-15.2zM138.4 50.3v.5h2.6v.5M138.4 48.3h2.6l-2.6 5.1h2.6zM190.5 40.7h15.2v20.3h-15.2zM241.3 40.7h15.2v20.3h-15.2zM290.8 50.3v.5h2.6v.5M290.8 48.3h2.6l-2.6 5.1h2.6zM382.3 50.3v.5h2.5v.5M382.3 48.3h2.5l-2.5 5.1h2.5zM149.9 62.3h2.5v15.2h-2.5zM302.3 62.3h2.5v15.2h-2.5z"/>
<path d="M393.7 62.3h2.5v15.2h-2.5zM359.4 116.9h5.1v38.1h-5.1zM38.1 129.6h15.2v20.3h-15.2zM125.7 139.7h5.1v7.7h-5.1zM213.4 139.7h5v7.7h-5zM231.1 130.3v.5h2.6v.6M231.1 128.3h2.6l-2.6 5.1h2.6zM213.4 175.6h5v2h-5zM359.4 165.1h5.1v76.2h-5.1zM47 194.3h-3.8a3.7 3.7 0 0 0-2.5 2.6 3.7 3.7 0 0 0 2.5 2.5h3.8a4 4 0 0 1 0-5M123.2 194.3h-3.8a3.7 3.7 0 0 0-2.5 2.6 3.7 3.7 0 0 0 2.5 2.5h3.8a4 4 0 0 1 0-5M206.5 195.1a2.55 2.55 0 0 1 1.8-.8h3.8v5.1h-3.8a2.54 2.54 0 0 1-2.4-1.5 2.54 2.54 0 0 1 .6-2.8z"/>
<path d="M53.6 202h2v5h-2zM58.7 202h2v5h-2zM129.8 202h2v5h-2zM134.9 202h2v5h-2zM218.7 202h2v5h-2zM223.8 202h2v5h-2zM213.4 220h5v2h-5zM41.4 258.6a2.55 2.55 0 0 1 1.8-.8h3.8v5.1h-3.8a2.54 2.54 0 0 1-2.4-1.5 2.54 2.54 0 0 1 .6-2.8zM117.6 258.6a2.55 2.55 0 0 1 1.8-.8h3.8v5.1h-3.8a2.54 2.54 0 0 1-2.4-1.5 2.54 2.54 0 0 1 .6-2.8zM53.6 265.5h2v5h-2zM58.7 265.5h2v5h-2zM129.8 265.5h2v5h-2z"/>
<path d="M134.9 265.5h2v5h-2z"/>
</g>
<g fill="#ffffc2" stroke="#ffffc2" stroke-width=".18">
<path d="M125.7 139.7h5.1v7.7h-5.1z"/>
<path d="M213.4 139.7h5v7.7h-5z"/>
<path d="M393.7 62.3h2.5v15.2h-2.5z"/>
<path d="M302.3 62.3h2.5v15.2h-2.5z"/>
<path d="M359.4 116.9h5.1v38.1h-5.1z"/>
<path d="M359.4 165.1h5.1v76.2h-5.1z"/>
<path d="M38.1 129.6h15.2v20.3h-15.2z"/>
<path d="M149.9 62.3h2.5v15.2h-2.5z"/>
<path d="M43.2 199.4h3.8z"/>
<path d="M43.2 194.3h3.8z"/>
<path d="M119.4 199.4h3.8z"/>
<path d="M119.4 194.3h3.8z"/>
<path d="M88.9 40.7h15.2v20.3h-15.2z"/>
<path d="M241.3 40.7h15.2v20.3h-15.2z"/>
<path d="M38.1 40.7h15.2v20.3h-15.2z"/>
<path d="M190.5 40.7h15.2v20.3h-15.2z"/>
</g>
<g fill="none" stroke="#008484" stroke-width=".18">
<path d="M123 50.7l.6-.1v-.4l-.6-.2v1.3M136.8 50.2l.1-.2a.67 .67 0 0 1 .5 .7 .67 .67 0 0 1-.5 .6l-.3-.5zM138.3 57.5l-.5-.1-.2 .1v.4l.6 .2 .1 .3-.2 .3-.5-.1M159.8 57.4v1.3l-.7-1.3v1.3M160.3 57.2a1.47 1.47 0 0 1 0 1.9M275.4 50.7l.6-.1v-.4l-.6-.2v1.3M289.2 50.2l.1-.2a.67 .67 0 0 1 .5 .7 .67 .67 0 0 1-.5 .6l-.3-.5zM290.7 57.5l-.5-.1-.2 .1v.4l.6 .2 .1 .3-.2 .3-.5-.1M312.2 57.4v1.3l-.7-1.3v1.3M312.7 57.2a1.47 1.47 0 0 1 0 1.9M366.8 50.7l.7-.1v-.4l-.7-.2v1.3M380.6 50.2l.2-.2a.67 .67 0 0 1 .4 .7 .67 .67 0 0 1-.4 .6l-.3-.5z"/>
<path d="M382.1 57.5l-.4-.1-.2 .1v.4l.5 .2 .1 .3-.2 .3-.5-.1M403.6 57.4v1.3l-.7-1.3v1.3M404.1 57.2a1.47 1.47 0 0 1 0 1.9M107.1 80.5h-.6v.6l.1-.1 .5 .1v.6l-.2 .1-.4-.1M207.9 81.9h-.6l-.1 .6 .2-.1 .4 .1 .1 .6-.2 .1-.5-.1M348.8 81.9h-.6v.6l.2-.1 .4 .1v.6l-.1 .1-.5-.1M348.1 112a.64 .64 0 0 1 .7 .6 .64 .64 0 0 1-.7 .7zM349.3 112.6h.5M349.9 112h-.6v1.3M374.3 112.4l.4-.4v1.3M374.3 113.3h.7M375.5 111.8a1.47 1.47 0 0 1 0 2"/>
<path d="M234.8 130.7l.7-.1v-.4l-.7-.1v1.2M248.6 130.2l.2-.1a.67 .67 0 0 1 .4 .6 .67 .67 0 0 1-.4 .6l-.3-.5zM165.8 151.8h-.6v.6l.1-.1h.5v.6l-.2 .1-.4-.1M205.2 151.6h-.7v.7l.2-.2 .4 .1 .1 .6-.2 .1-.5-.1M351.1 160.3a.64 .64 0 0 1 .7 .6 .64 .64 0 0 1-.7 .6zM352.3 160.9h.5M352.9 160.3h-.6v1.2M371.3 160.6l.4-.3v1.2M371.3 161.5h.7M372.5 160.1a1.47 1.47 0 0 1 0 1.9"/>
</g>
<path d="M355 115.6l.4-1.3 .5 1.3M355.1 115.2h.6M368.1 114.9l.2-.2 .3 .1 .1 .8M368.1 114.7v.9M355 163.8l.4-1.2 .5 1.2M355.1 163.5h.6M368.1 163.1l.2-.1 .3 .1 .1 .7M368.1 163v.8" fill="none" stroke="#840084" stroke-width=".18"/>
<path d="M50 187.2v4.1M51.6 187.2v4.1M126.2 187.2v4.1M127.8 187.2v4.1M215.1 187.2v4.1M216.7 187.2v4.1M50 250.7v4.1M51.6 250.7v4.1M126.2 250.7v4.1M127.8 250.7v4.1" fill="none" stroke="#840000" stroke-width=".51"/>
<path d="M40.1 34.1v3M50.3 34.1v3M90.9 34.1v3M101.1 34.1v3M192.5 34.1v3M202.7 34.1v3M243.3 34.1v3M253.5 34.1v3M40.1 123v3M50.3 123v3" fill="none" stroke="#840000" stroke-width=".33"/>
<path d="M165.1 12.7v88.9M317.5 12.7v240.1M12.7 101.6h395M177.8 101.6v182.9M254 101.6v63.5M12.7 165.1h304.8M12.7 228.6h304.8M88.9 228.6v55.9M177.8 254h121.9" fill="none" stroke="#0000c2" stroke-width=".25" stroke-dasharray=".6 .6"/>
<g fill="none" stroke="#0000c2" stroke-width=".18" stroke-dasharray="0 .4">
<path d="M53.3 77.5h66.1M119.4 77.5v7.6M189.2 77.5h82.6M271.8 77.5v7.6M372.1 77.5h-41.9M372.1 77.5v7.6M53.3 85.1v-7.6M119.4 85.1h-66.1M189.2 85.1v-7.6M271.8 85.1h-82.6M330.2 85.1h41.9M330.2 85.1v-7.6"/>
<path d="M160 139.7v10.2M170.2 139.7h-10.2M86.4 142.3v11.4M86.4 153.7h83.8M86.4 142.3h10.1M96.5 149.9v-7.6M160 149.9h-63.5M170.2 153.7v-14M184.1 142.3v11.4M184.1 153.7h61M198.1 149.9v-7.6M198.1 142.3h-14"/>
<path d="M233.7 149.9h-35.6M233.7 142.3v7.6M245.1 153.7v-11.4M245.1 142.3h-11.4"/>
</g>
<g fill="none" stroke="#008400" stroke-width=".18">
<path d="M35.6 38.1h7.6M38.1 35.6h-1.3v2.5M43.2 35.6h5.1M45.7 34.3v1.3M48.3 38.1h7.6M53.3 35.6h1.3v2.5M86.4 38.1h7.6M88.9 35.6h-1.3v2.5M94 35.6h5.1M96.5 34.3v1.3M99.1 38.1h7.6M104.1 35.6h1.3v2.5"/>
<path d="M188 38.1h7.6M190.5 35.6h-1.3v2.5M195.6 35.6h5.1M198.1 34.3v1.3M200.7 38.1h7.6M205.7 35.6h1.3v2.5M238.8 38.1h7.6M241.3 35.6h-1.3v2.5M246.4 35.6h5.1M248.9 34.3v1.3M251.5 38.1h7.6M256.5 35.6h1.3v2.5"/>
<path d="M27.9 58.5h7.7M27.9 48.3h7.7M27.9 53.4h7.7M55.9 48.3h8.9v29.2M55.9 53.4h1.2v24.1M72.4 48.3h14M72.4 53.4h14M78.7 58.5h7.7M106.7 48.3h8.9v29.2M106.7 53.4h2.5v24.1M139.7 45.8v1.2M139.7 54.6v8.9"/>
<path d="M180.3 58.5h7.7M180.3 48.3h7.7M180.3 53.4h7.7M208.3 48.3h8.9v29.2M208.3 53.4h1.2v24.1M231.1 58.5h7.7M233.7 48.3h5.1M233.7 53.4h5.1M259.1 48.3h8.9v29.2M259.1 53.4h2.5v24.1M284.5 59.7h7.6M292.1 45.8v1.2"/>
<path d="M292.1 54.6v8.9h6.3M375.9 59.7h7.6M383.5 45.8v1.2M383.5 54.6v8.9h6.4M45.7 63.5v1.3M57.1 73.7h88.9M64.8 68.6h81.2M96.5 63.5v1.3M109.2 76.2h36.8M115.6 71.2h30.4M132.1 63.5h13.9M134.6 66.1h11.4"/>
<path d="M198.1 63.5v1.3M209.5 71.2h88.9M217.2 68.6h81.2M248.9 63.5v1.3M261.6 73.7h36.8M268 66.1h30.4M298.4 76.2h-6.3v5.1M331.5 66.1h58.4M331.5 73.7h58.4M331.5 71.2h58.4M331.5 68.6h58.4M350.5 73.7v3.8"/>
<path d="M355.6 71.2v6.3M361.9 68.6v8.9M368.3 66.1v11.4M389.9 76.2h-6.4v5.1M109.2 82.6v3.8M209.5 82.6v3.8M350.5 82.6v3.8M196.8 116.9h19.1M196.8 119.4h19.1M273 114.3h31.8M342.9 118.1h12.7M368.3 118.1h12.7"/>
<path d="M27.9 137.2h7.7M35.6 127h7.6M38.1 124.5h-1.3v2.5M43.2 124.5h5.1M45.7 123.2v1.3M48.3 127h7.6M53.3 124.5h1.3v2.5M55.9 137.2h16.5M196.8 122h19.1M196.8 124.5h19.1M232.4 125.8v1.2M232.4 134.7v6.3"/>
<path d="M273 139.7h31.8M273 130.8h31.8M273 127h31.8M273 123.2h31.8M342.9 130.8h12.7M342.9 120.7h12.7M342.9 128.3h12.7M342.9 133.4h12.7M342.9 138.5h12.7M368.3 130.8h12.7M368.3 120.7h12.7M368.3 128.3h12.7"/>
<path d="M368.3 133.4h12.7M368.3 125.8h12.7M27.9 147.4h7.7M27.9 142.3h7.7M45.7 152.4v1.3M55.9 142.3h16.5M96.5 143.5h25.4M96.5 141h25.4M96.5 146.1h25.4M134.6 143.5h25.4M134.6 141h25.4M134.6 146.1h25.4"/>
<path d="M165.1 146.1h2.5v8.9M191.8 143.5h-5.1v11.5M196.8 143.5h12.7M196.8 141h12.7M196.8 146.1h12.7M222.2 143.5h12.7M222.2 141h12.7M222.2 146.1h12.7M273 147.4h31.8M342.9 141h12.7M342.9 146.1h12.7M342.9 148.6h12.7"/>
<path d="M342.9 151.2h12.7M342.9 153.7h12.7M368.3 143.5h12.7M191.8 176.6h20.3M219.7 176.6h29.2M273 171.5h31.8M273 175.3h31.8M342.9 176.6h12.7M342.9 179.1h12.7M368.3 179.1h12.7M368.3 174h12.7M368.3 168.9h12.7"/>
<path d="M31.7 196.9h5.1M43.2 189.3h3.8M43.2 188v6.3M43.2 199.4v1.3M50.8 195.6h25.4M50.8 198.2h25.4M54.6 189.3h1.3M54.6 198.2v2.5M59.7 195.6v5.1M107.9 196.9h5.1M119.4 189.3h3.8M119.4 188v6.3"/>
<path d="M119.4 199.4v1.3M127 195.6h25.4M127 198.2h25.4M130.8 189.3h1.3M130.8 198.2v2.5M135.9 195.6v5.1M191.8 196.9h10.1M198.1 196.9v24.1h14M208.3 189.3h3.8M208.3 188v6.3M208.3 199.4v1.3M215.9 195.6h33"/>
<path d="M215.9 198.2h33M219.7 189.3h1.3M219.7 198.2v2.5M224.8 195.6v5.1M233.7 198.2v22.8h-14M273 180.4h31.8M273 184.2h31.8M368.3 186.7h12.7M54.6 208.3v1.3M59.7 208.3v1.3M130.8 208.3v1.3M135.9 208.3v1.3"/>
<path d="M219.7 208.3v1.3M224.8 208.3v1.3M342.9 202h12.7M368.3 209.6h12.7M368.3 202h12.7M368.3 219.7h12.7M368.3 217.2h12.7M342.9 237.5h12.7M368.3 227.4h12.7M368.3 237.5h12.7M43.2 251.5v6.3M43.2 252.8h3.8"/>
<path d="M50.8 259.1h25.4M54.6 252.8h1.3M59.7 259.1v5.1M119.4 251.5v6.3M119.4 252.8h3.8M127 259.1h22.9M130.8 252.8h1.3M135.9 259.1v5.1M196.8 241.3h19.1M342.9 240.1h12.7M31.7 260.4h5.1M43.2 262.9v1.3"/>
<path d="M50.8 261.7h25.4M54.6 261.7v2.5M54.6 271.8v1.3M59.7 271.8v1.3M107.9 260.4h5.1M119.4 262.9v1.3M127 261.7h22.9M130.8 261.7v2.5M130.8 271.8v1.3M135.9 271.8v1.3"/>
</g>
<g fill="none" stroke="#848400" stroke-width=".25">
<path d="M55.9 38.1l.6-.6h.6v1.3h-.6zM107.3 37.5h.6v1.3h-.6l-.6-.7zM208.9 37.5h.6v1.3h-.6l-.6-.7zM259.7 37.5h.6v1.3h-.6l-.6-.7zM26.7 52.7h.6l.6 .7-.6 .6h-.6zM26.7 47.7h.6l.6 .6-.6 .6h-.6zM179.1 52.7h.6l.6 .7-.6 .6h-.6zM179.1 47.7h.6l.6 .6-.6 .6h-.6zM233 52.7h.7v1.3h-.7l-.6-.6zM233 47.7h.7v1.2h-.7l-.6-.6zM283.8 59.1h.7v1.3h-.7l-.6-.7zM375.3 59.1h.6v1.3h-.6l-.7-.7z"/>
<path d="M131.4 62.9h.7v1.3h-.7l-.6-.7zM330.2 70.5h.6l.7 .7-.7 .6h-.6zM330.2 68h.6l.7 .6-.7 .7h-.6zM330.8 65.4h.7v1.3h-.7l-.6-.6zM330.8 73.1h.7v1.2h-.7l-.6-.6zM195.6 119.4l.6-.6h.6v1.3h-.6zM195.6 116.9l.6-.7h.6v1.3h-.6zM271.8 113.7h.6l.6 .6-.6 .7h-.6zM26.7 136.6h.6l.6 .6-.6 .6h-.6zM56.5 126.4h.6v1.3h-.6l-.6-.7zM195.6 121.3h.6l.6 .7-.6 .6h-.6zM195.6 124.5l.6-.6 .6 .6-.6 .6z"/>
<path d="M271.8 122.6h.6l.6 .6-.6 .7h-.6zM271.8 126.4h.6l.6 .6-.6 .7h-.6zM271.8 139.1h.6l.6 .6-.6 .7h-.6zM271.8 130.2h.6l.6 .6-.6 .7h-.6zM26.7 141.6h.6l.6 .7-.6 .6h-.6zM271.8 146.7h.6l.6 .7-.6 .6h-.6zM190.5 175.9h.6l.7 .7-.7 .6h-.6zM271.8 174.7h.6l.6 .6-.6 .6h-.6zM271.8 179.7h.6l.6 .7-.6 .6h-.6zM272.4 170.9h.6v1.2h-.6l-.6-.6zM30.5 196.9l.6-.6h.6v1.2h-.6zM107.3 196.3h.6v1.2h-.6l-.6-.6z"/>
<path d="M191.1 196.3h.7v1.2h-.7l-.6-.6zM272.4 183.6h.6v1.2h-.6l-.6-.6zM31.1 259.8h.6v1.2h-.6l-.6-.6zM107.3 259.8h.6v1.2h-.6l-.6-.6zM196.2 240.7h.6v1.3h-.6l-.6-.7z"/>
</g>
<path d="M349.3 147.6l.2-.1h.3l.1 .8M349.4 236.5h.5l.1-.4-.6-.2v1.3h.5l.1-.1 .1-.3-.3-.3" fill="none" stroke="#000" stroke-width=".18"/>
<g fill="none" stroke="#0000c2" stroke-width=".18">
<path d="M33.5 59.8h.4M33.6 59.4v1.1l.3 .2M84.3 59.8h.4M84.4 59.4v1.1l.3 .2M185.9 59.8h.4M186 59.4v1.1l.3 .2M236.7 59.8h.4M236.8 59.4v1.1l.3 .2M154 109.5l.2-.1h.3l.1 .8M154 108.9v1.3M155.1 109.8l.6-.1v-.3h-.4l-.2 .1 .1 .6h.5M156.3 109.4h.5v.8"/>
<path d="M156.8 109.7h-.4l-.2 .2 .2 .3 .4-.1M158 109.4h-.4l-.2 .2 .1 .5h.5M158 108.9v1.3M158.5 109.8l.6-.1v-.3h-.4l-.2 .1 .1 .6h.5M159.7 109.4v.8M159.8 107.4h.5v.7M160 109.4l-.3 .2M160.3 107.6l-.4 .1-.2 .1 .2 .3h.4M160.5 110.1v.1M162.3 107.4l-.3-.1-.2 .2 .1 .2 .4 .1v.3h-.5M162.7 107.3h.5M162.9 106.9v1.1l.3 .1"/>
<path d="M163.7 107.4h.4l.1 .7M164.2 107.6l-.4 .1-.2 .1 .1 .3h.5M164.8 107.4l.2-.1 .3 .1 .1 .7M164.8 107.3v.8M165.9 106v.1M166.5 107.4l-.4-.1-.2 .2 .1 .6h.5M166.5 106.9v1.2M167.1 107.4h.5v.7M167.5 104.8v1.3M167.5 105.4h.7M167.6 107.6l-.4 .1-.2 .1 .2 .3h.4M168.2 104.8v1.3"/>
<path d="M168.2 107.3v.8M168.6 107.3l-.4 .2M168.8 105.4l.2-.2 .3 .2 .1 .5-.1 .1-.3 .1-.2-.1zM169.6 107.4l-.4-.1-.2 .2 .1 .6h.5M169.6 106.9v1.2M169.8 105.2l.3 .9 .2-.6 .2 .6 .3-.9M171.2 105.6l.6-.1v-.2l-.4-.1-.2 .2 .1 .6h.5M172.2 105.2l.3 .9 .3-.9M173.3 105.6l.6-.1-.1-.2-.3-.1-.2 .2v.6h.5M174.4 105.2v.9M174.8 105.2l-.4 .3M373.6 121.6v1.1l.2 .2 .4-.1 .1-.1v-1.1"/>
<path d="M33.5 148.7h.4M33.6 148.3v1.1l.3 .2M25.4 178.8h.8l-.4 .5 .3 .1v.5l-.1 .1-.6-.1M26.4 174.7h.8l-.4 .4 .4 .2v.4l-.2 .2-.6-.1M26.5 178.8l.5 1.2 .4-1.2M27.6 174.7l.4 1.2 .4-1.2M27.7 178.8h.8l-.4 .5 .3 .1 .1 .4-.3 .2-.5-.1M28.7 174.7h.8l-.4 .4 .4 .2v.5l-.2 .1-.6-.1M31 177.3l.1-.1 .4 .1 .1 .5-.2 .1-.3 .1-.1-.1zM32.1 177.2v.8M32.5 177.2l-.4 .2M34.5 176.7h-.6l-.1 .6 .5-.1 .2 .3v.3l-.2 .2-.5-.1"/>
<path d="M34.9 176.7l.4 1.3 .4-1.3M36.7 172.6v1.1l.2 .2M37.4 173.1h.5v.8M37.9 173.3l-.4 .1-.2 .2 .2 .3 .4-.1M38.4 173h.4M38.5 172.6v1.1l.3 .2M39.2 172.6v.1M39.2 173v.9M39.9 173.2l.1-.2 .4 .2 .1 .4-.2 .2-.3 .1-.1-.2zM41 173.2l.2-.2 .3 .1 .1 .8M41 173v.9M42.2 173.7v.2"/>
<path d="M42.2 173.1v.1M30 238.2h.8l-.4 .4 .4 .2-.1 .6h-.4l-.3-.1M31.2 238.2l.4 1.2 .5-1.2M32.4 238.2h.7l-.4 .4 .4 .2v.5l-.2 .1-.5-.1M39.2 236.1v1.1l.2 .2M39.9 236.6h.5l.1 .8M40.5 236.8l-.5 .1-.1 .2 .1 .3 .5-.1M40.9 236.5h.5M41.1 236.1v1.1l.3 .2M41.8 236.1v.1M41.8 236.5v.9M42.5 236.6l.2-.1 .3 .2v.4l-.1 .2-.3 .1-.2-.2-.1-.4z"/>
<path d="M43.5 236.7l.2-.2 .3 .1 .1 .8M43.5 236.5v.9M44.7 237.2v.2M44.7 236.6v.1M102.3 238.2h.7l-.4 .4 .4 .2-.1 .6h-.5l-.1-.1M103.4 238.2l.4 1.2 .5-1.2M104.6 238.2h.8l-.5 .4 .4 .2 .1 .4-.3 .2-.5-.1M114.2 236.1v1.1l.2 .2M114.9 236.6h.4l.1 .8M115.4 236.8l-.4 .1-.2 .2 .2 .3 .4-.1M115.8 236.5h.5M116 236.1v1.1l.3 .2"/>
<path d="M116.7 236.1v.1M116.7 236.5v.9M117.3 236.7l.2-.2 .4 .2v.4l-.1 .2-.3 .1-.2-.2zM118.5 236.7l.2-.2 .2 .1 .1 .8M118.5 236.5v.9M119.6 237.2v.2M119.6 236.6v.1M302.2 225l-.4-.1-.2 .3 .1 .5h.5M302.2 224.5v1.3M302.8 224.9l.1 .8 .3 .1 .2-.2M303.4 224.9v.9M304 224.5v1.1l.1 .2"/>
<path d="M304.6 225.3l.6-.1-.1-.2-.4-.1-.1 .2v.6h.5M305.7 223l.2-.1h.3v.8M306.1 225l-.3-.1-.2 .2 .1 .2 .4 .1v.3h-.5M306.7 225.6v.2M306.9 222.4v.2M306.9 222.9v.8M308 222.9h-.4l-.2 .2 .1 .6h.5M308.2 220.8l.1 .8 .3 .1 .1-.2M308.6 222.9h.4l.1 .8M308.7 220.8v.9M309.1 223.2h-.4l-.2 .2 .1 .3h.5M309.5 222.9h.5"/>
<path d="M309.7 222.4v1.1l.3 .2M309.8 220.9l-.4-.1-.1 .2v.2l.5 .1v.3h-.5M310.3 221.2l.6-.1-.1-.2-.3-.1-.2 .2 .1 .6h.4M310.4 222.4v.2M310.4 222.9v.8M311 223l.2-.1 .4 .1v.5l-.1 .2h-.3l-.2-.1zM312 220.9l-.4-.1-.2 .2 .1 .6h.5M312 220.4v1.3M312.2 223l.2-.1h.3v.8M312.2 222.9v.8M313.4 220.8h.5M313.6 220.4v1.1l.3 .2"/>
<path d="M314.4 220.9l.3-.1 .2 .2-.1 .6-.3 .1-.2-.2zM31 242.3h.8l-.4 .5 .3 .1 .1 .4-.2 .2-.6-.1M32.2 242.3l.4 1.2 .4-1.2M33.3 242.3h.8l-.4 .5 .4 .1v.5l-.2 .1-.6-.1M41.2 240.7v.8M41.6 240.7h-.3l-.1 .2M43.5 240.2h-.5l-.1 .6 .5-.1 .2 .3v.3l-.2 .2-.5-.1M44 240.2l.4 1.3 .4-1.3M104.8 242.3l.4 1.2 .5-1.2M106 242.3h.8l-.5 .5 .4 .1 .1 .4-.3 .2-.5-.1M114.2 240.7l-.4 .2M116.2 240.2h-.6l-.1 .6 .2-.1 .4 .1 .1 .6-.2 .1-.5-.1"/>
<path d="M116.6 240.2l.4 1.3 .4-1.3"/>
</g>
<g fill="none" stroke="#0000c2" stroke-width=".38">
<path d="M60.7 15.6l-.3-.1-.7 .1a.46 .46 0 0 0-.1 .4 .46 .46 0 0 0 .3 .4 .68 .68 0 0 1 .8 .4l-.1 .4-.3 .2-.7-.1M61.2 15.5h1.1M61.7 15.5v1.9M62.9 17.4v-1.9l.7 1.3 .6-1.3v1.9M64.9 15.7l.5 .2 .4-.2M65.1 16.3l.3-.4 .2 .4M65.4 15.5v.4M214 15.6a.79 .79 0 0 0-1 0l-.1 .2a.46 .46 0 0 0 .3 .6 .66 .66 0 0 1 .8 .6l-.4 .4-.7-.1M214.5 15.5h1.1M215 15.5v1.9M216.1 15.5l.4 1.9 .4-1.4 .3 1.4 .5-1.9M218.2 15.7l.5 .2 .4-.2"/>
<path d="M218.4 16.3l.3-.4 .2 .4M218.7 15.5v.4M366.4 15.5v1.3a.64 .64 0 0 1-.7 .6M368.4 15.6a.76 .76 0 0 0-1 0 .45 .45 0 0 0 .2 .8 .67 .67 0 0 1 .8 .4l-.1 .4a.79 .79 0 0 1-1 .1M368.9 15.5h1.1M369.4 15.5v1.9M370.6 16.4h.7a.51 .51 0 0 0 .4-.5 .51 .51 0 0 0-.4-.4h-.7v1.9M372.3 15.7l.5 .2 .5-.2M372.5 16.3l.3-.4 .3 .4M372.8 15.5v.4M68.2 105.2a.47 .47 0 0 1 .8 .1v1M68.2 104.4v1.9"/>
<path d="M69.8 105.6l.9-.2-.1-.3-.5-.1-.3 .3 .1 .9 .2 .1 .5-.1M71.5 105.1l.2-.1 .6 .1 .1 1.2M72.4 105.4l-.7 .1a.38 .38 0 0 0-.3 .4 .38 .38 0 0 0 .3 .4l.7-.1M74.1 105.1l-.6-.1-.3 .3 .1 .8 .2 .2 .6-.1M74.1 104.4v1.9M74.9 105.6l.9-.2-.1-.3-.5-.1-.3 .3 .1 .9 .2 .1 .5-.1M76.6 105v1.3M77.2 105l-.4 .1-.2 .2M230.9 105.2a.49 .49 0 0 1 .8 .1v1M230.9 104.4v1.9M232.6 105.6l.9-.2-.1-.3-.6-.1-.2 .3v.9l.2 .1 .6-.1M234.3 105.1l.2-.1 .5 .1 .1 1.2"/>
<path d="M235.1 105.4l-.6 .1a.38 .38 0 0 0-.3 .4 .38 .38 0 0 0 .3 .4l.6-.1M236.8 105.1a.62 .62 0 0 0-.8 .1v.9a.62 .62 0 0 0 .8 .1M236.8 104.4v1.9M237.6 105.6l.9-.2v-.3l-.6-.1-.3 .3 .1 .9 .2 .1 .6-.1M239.4 105v1.3M239.9 105l-.4 .1-.1 .2M272.6 105l.4 1.3M273.5 105l-.7 1.7-.2 .2M346.2 106.4l-.4-.1-.3 .2 .1 .3 .6 .2v.4l-.2 .1-.5-.1M51.8 168.7a.47 .47 0 0 1 .8 .1v1M51.8 168.5v1.3M54.3 168.5v1.5a.52 .52 0 0 1-.8 .3"/>
<path d="M54.3 168.6l-.6-.1-.3 .3v.6l.2 .3 .1 .1 .6-.1M204.5 168.7a.47 .47 0 0 1 .8 .1v1M207.1 168.5v1.5a.52 .52 0 0 1-.9 .3M207.1 168.6l-.2-.1a.63 .63 0 0 0-.8 .3v.6a.61 .61 0 0 0 1 .3M42.1 232.2a.47 .47 0 0 1 .9 .1v1M44.7 232v1.5a.52 .52 0 0 1-.8 .3M44.7 232.1l-.6-.1-.3 .3 .1 .8 .2 .2 .6-.1M118.7 232.2a.48 .48 0 0 1 .7-.1l.1 1.2M121.3 232l-.1 1.7a.52 .52 0 0 1-.8 .1M121.3 232.1a.62 .62 0 0 0-.9 .1v.9a.62 .62 0 0 0 .9 .1M205.9 233.3l.1 1.1a.52 .52 0 0 0 .7 0M206.7 233.3v1.2"/>
<path d="M207.3 233.3h.8M207.6 232.6v1.7l.1 .1 .4 .1"/>
</g>
<g fill="#008400" stroke="#008400" stroke-width=".25">
<circle cx="219.7" cy="198.2" r=".51"/>
<circle cx="64.8" cy="68.6" r=".51"/>
<circle cx="232.4" cy="141" r=".51"/>
<circle cx="57.2" cy="73.7" r=".51"/>
<circle cx="139.7" cy="63.5" r=".51"/>
<circle cx="115.6" cy="71.2" r=".51"/>
<circle cx="109.2" cy="76.2" r=".51"/>
<circle cx="59.7" cy="195.6" r=".51"/>
<circle cx="368.3" cy="66.1" r=".51"/>
<circle cx="361.9" cy="68.6" r=".51"/>
<circle cx="355.6" cy="71.2" r=".51"/>
<circle cx="268" cy="66.1" r=".51"/>
<circle cx="350.5" cy="73.7" r=".51"/>
<circle cx="209.6" cy="71.2" r=".51"/>
<circle cx="54.6" cy="127" r=".51"/>
<circle cx="36.8" cy="127" r=".51"/>
<circle cx="45.7" cy="124.5" r=".51"/>
<circle cx="261.6" cy="73.7" r=".51"/>
<circle cx="217.2" cy="68.6" r=".51"/>
<circle cx="54.6" cy="38.1" r=".51"/>
<circle cx="233.7" cy="198.2" r=".51"/>
<circle cx="240" cy="38.1" r=".51"/>
<circle cx="54.6" cy="198.2" r=".51"/>
<circle cx="257.8" cy="38.1" r=".51"/>
<circle cx="43.2" cy="189.3" r=".51"/>
<circle cx="96.5" cy="35.6" r=".51"/>
<circle cx="198.1" cy="35.6" r=".51"/>
<circle cx="130.8" cy="198.2" r=".51"/>
<circle cx="135.9" cy="195.6" r=".51"/>
<circle cx="119.4" cy="189.3" r=".51"/>
<circle cx="54.6" cy="261.7" r=".51"/>
<circle cx="189.2" cy="38.1" r=".51"/>
<circle cx="43.2" cy="252.8" r=".51"/>
<circle cx="207" cy="38.1" r=".51"/>
<circle cx="248.9" cy="35.6" r=".51"/>
<circle cx="130.8" cy="261.7" r=".51"/>
<circle cx="36.8" cy="38.1" r=".51"/>
<circle cx="119.4" cy="252.8" r=".51"/>
<circle cx="292.1" cy="59.7" r=".51"/>
<circle cx="383.5" cy="59.7" r=".51"/>
<circle cx="59.7" cy="259.1" r=".51"/>
<circle cx="135.9" cy="259.1" r=".51"/>
<circle cx="45.7" cy="35.6" r=".51"/>
<circle cx="105.4" cy="38.1" r=".51"/>
<circle cx="208.3" cy="189.3" r=".51"/>
<circle cx="87.6" cy="38.1" r=".51"/>
<circle cx="224.8" cy="195.6" r=".51"/>
<circle cx="198.1" cy="196.9" r=".51"/>
</g>
<g fill="none" stroke="#000084" stroke-width=".18">
<path d="M75.6 80.7l1.2 1.2M76.8 80.7l-1.2 1.2M238.2 80.7l1.2 1.2M239.4 80.7l-1.2 1.2M355 135.3l1.2 1.2M355 122.6l1.2 1.2M355 125.2l1.2 1.2M356.2 135.3l-1.2 1.2M356.2 122.6l-1.2 1.2M356.2 125.2l-1.2 1.2M367.7 137.9l1.2 1.2M367.7 122.6l1.2 1.2"/>
<path d="M367.7 135.3l1.2 1.2M368.9 122.6l-1.2 1.2M368.9 135.3l-1.2 1.2M368.9 137.9l-1.2 1.2M355 142.9l1.2 1.3M356.2 142.9l-1.2 1.3M367.7 148l1.2 1.2M367.7 153.1l1.2 1.2M367.7 150.6l1.2 1.2M367.7 140.4l1.2 1.2M367.7 145.5l1.2 1.2M368.9 153.1l-1.2 1.2"/>
<path d="M368.9 150.6l-1.2 1.2M368.9 148l-1.2 1.2M368.9 140.4l-1.2 1.2M368.9 145.5l-1.2 1.2M355 170.9l1.2 1.2M355 168.3l1.2 1.3M355 173.4l1.2 1.2M355 165.8l1.2 1.2M356.2 165.8l-1.2 1.2M356.2 173.4l-1.2 1.2M356.2 170.9l-1.2 1.2M356.2 168.3l-1.2 1.3"/>
<path d="M367.7 165.8l1.2 1.2M367.7 170.9l1.2 1.2M367.7 176l1.2 1.2M368.9 165.8l-1.2 1.2M368.9 170.9l-1.2 1.2M368.9 176l-1.2 1.2M355 186.1l1.2 1.2M355 193.7l1.2 1.3M355 196.3l1.2 1.2M355 183.6l1.2 1.2M355 198.8l1.2 1.2M355 191.2l1.2 1.2"/>
<path d="M355 188.7l1.2 1.2M355 181l1.2 1.3M356.2 183.6l-1.2 1.2M356.2 188.7l-1.2 1.2M356.2 193.7l-1.2 1.3M356.2 196.3l-1.2 1.2M356.2 198.8l-1.2 1.2M356.2 191.2l-1.2 1.2M356.2 186.1l-1.2 1.2M356.2 181l-1.2 1.3M367.7 188.7l1.2 1.2M367.7 191.2l1.2 1.2"/>
<path d="M367.7 193.7l1.2 1.3M367.7 196.3l1.2 1.2M367.7 198.8l1.2 1.2M367.7 183.6l1.2 1.2M367.7 181l1.2 1.3M368.9 188.7l-1.2 1.2M368.9 191.2l-1.2 1.2M368.9 193.7l-1.2 1.3M368.9 196.3l-1.2 1.2M368.9 198.8l-1.2 1.2M368.9 181l-1.2 1.3M368.9 183.6l-1.2 1.2"/>
<path d="M355 211.5l1.2 1.2M355 203.9l1.2 1.2M355 206.4l1.2 1.3M355 209l1.2 1.2M355 219.1l1.2 1.3M355 216.6l1.2 1.2M355 214.1l1.2 1.2M356.2 203.9l-1.2 1.2M356.2 206.4l-1.2 1.3M356.2 209l-1.2 1.2M356.2 211.5l-1.2 1.2M356.2 216.6l-1.2 1.2"/>
<path d="M356.2 219.1l-1.2 1.3M356.2 214.1l-1.2 1.2M367.7 211.5l1.2 1.2M367.7 203.9l1.2 1.2M367.7 206.4l1.2 1.3M367.7 214.1l1.2 1.2M368.9 211.5l-1.2 1.2M368.9 203.9l-1.2 1.2M368.9 206.4l-1.2 1.3M368.9 214.1l-1.2 1.2M355 221.7l1.2 1.2M355 231.8l1.2 1.3"/>
<path d="M355 229.3l1.2 1.2M355 226.8l1.2 1.2M355 224.2l1.2 1.2M355 234.4l1.2 1.2M356.2 224.2l-1.2 1.2M356.2 234.4l-1.2 1.2M356.2 226.8l-1.2 1.2M356.2 231.8l-1.2 1.3M356.2 229.3l-1.2 1.2M356.2 221.7l-1.2 1.2M367.7 221.7l1.2 1.2M367.7 224.2l1.2 1.2"/>
<path d="M367.7 229.3l1.2 1.2M367.7 234.4l1.2 1.2M367.7 239.5l1.2 1.2M367.7 231.8l1.2 1.3M368.9 221.7l-1.2 1.2M368.9 224.2l-1.2 1.2M368.9 229.3l-1.2 1.2M368.9 234.4l-1.2 1.2M368.9 239.5l-1.2 1.2M368.9 231.8l-1.2 1.3"/>
</g>
<use href="#words"/>
</svg>
